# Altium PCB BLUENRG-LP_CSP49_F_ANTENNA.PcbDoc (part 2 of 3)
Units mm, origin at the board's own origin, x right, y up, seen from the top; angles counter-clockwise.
Board outline 90.84 x 54.03 mm, 4 copper layers (Top Layer, G1, G2, Bottom Layer), stack 1.697 mm thick; 159 components, 123 nets, 503 pads, 685 vias.

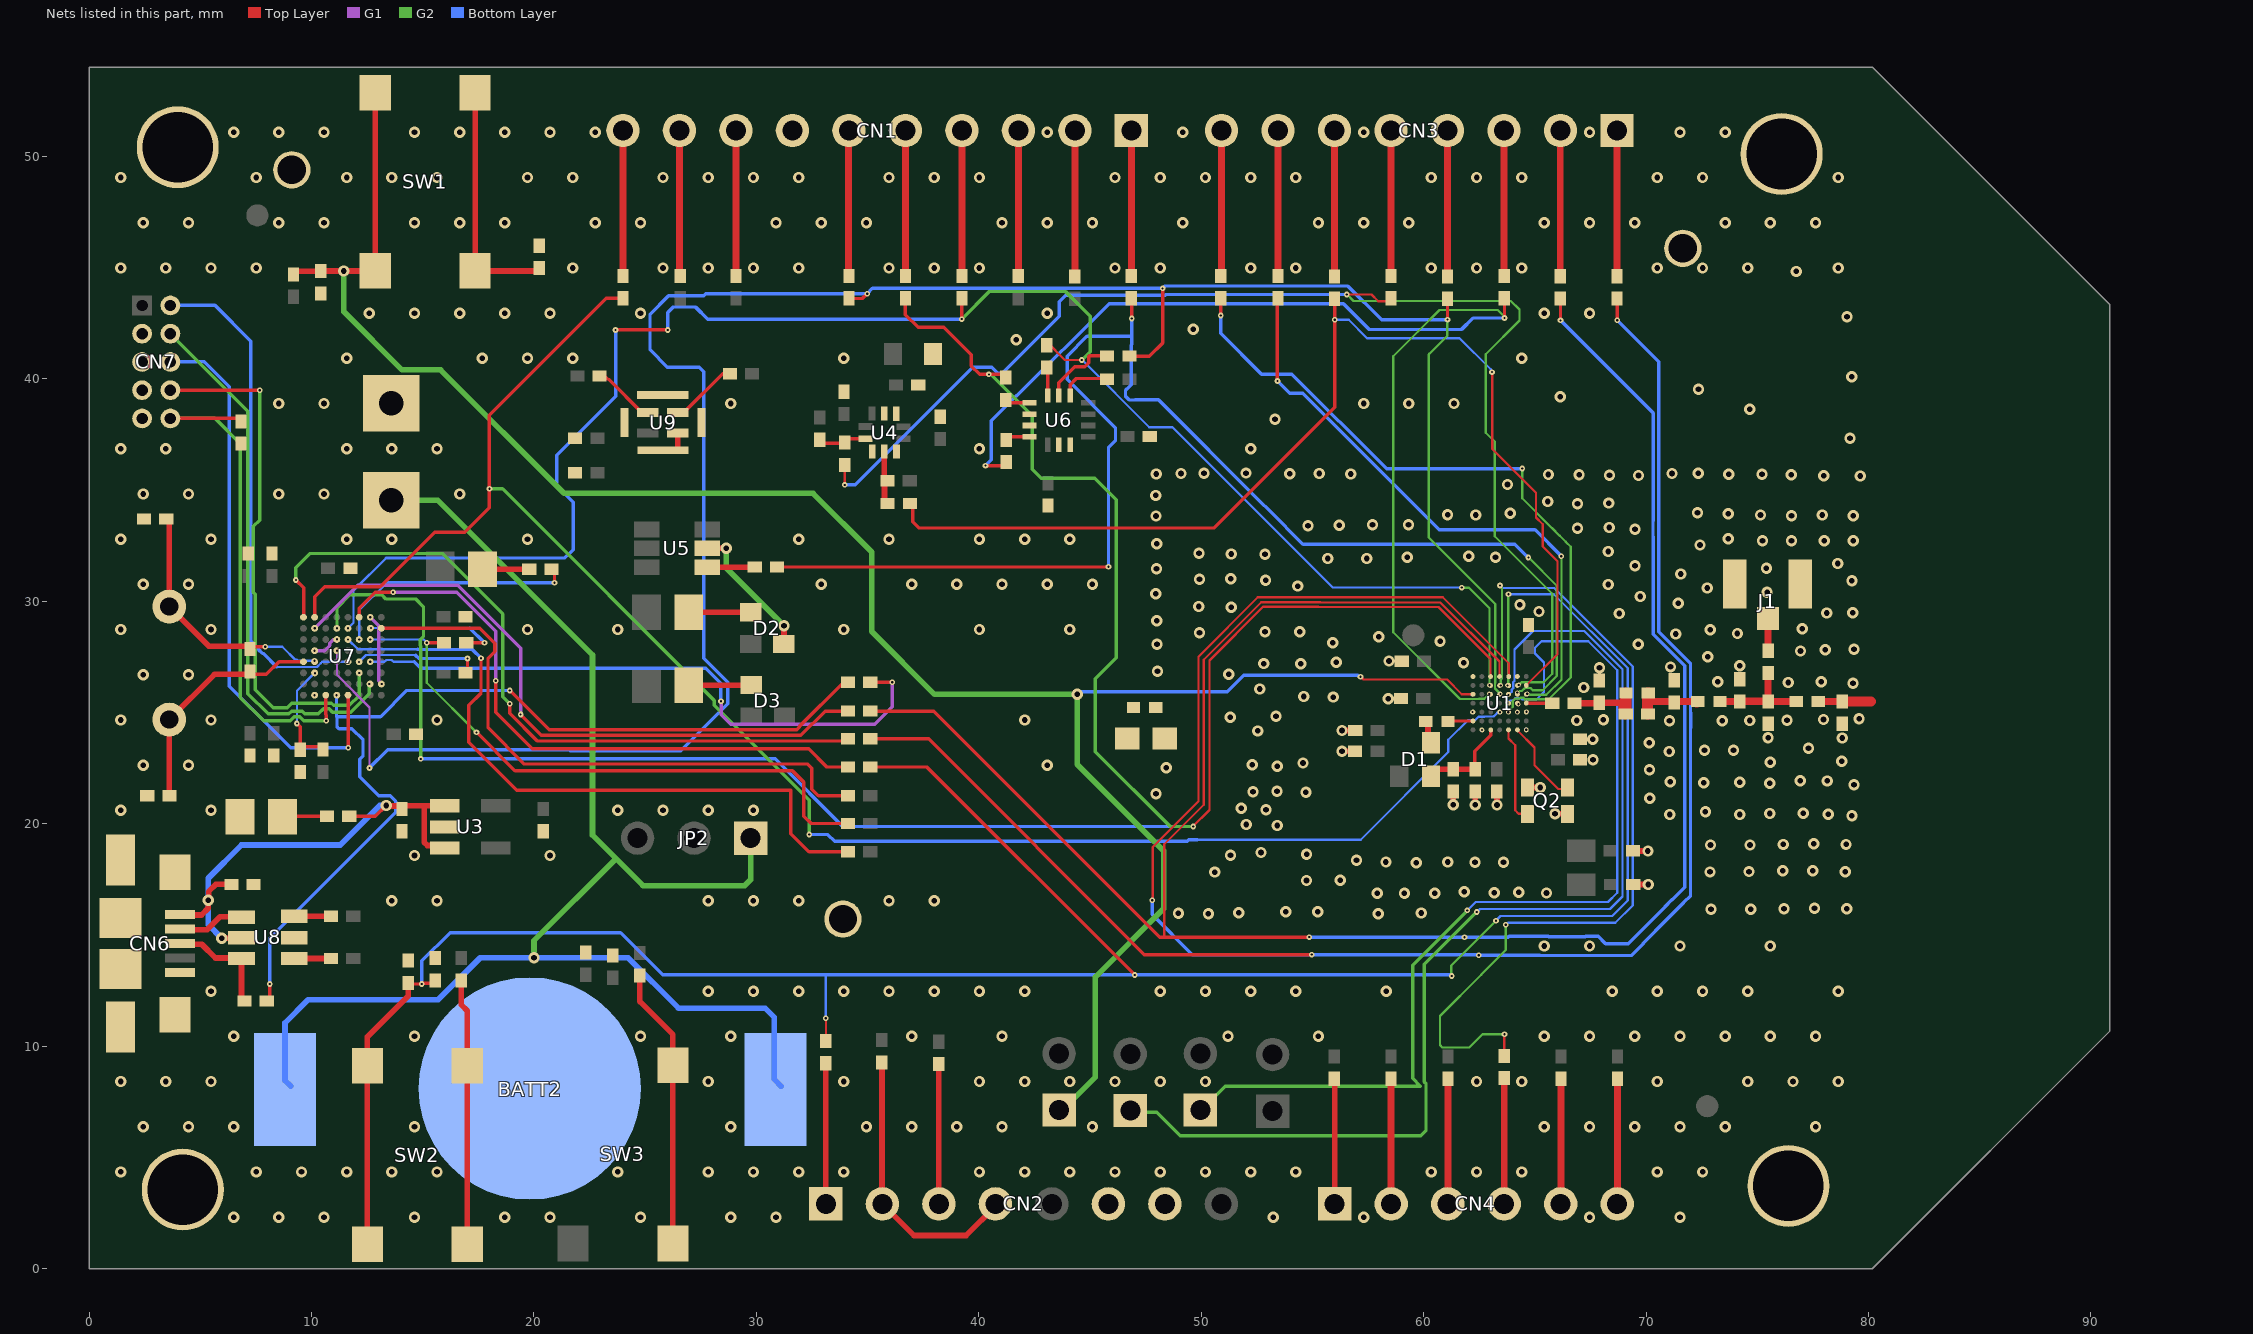
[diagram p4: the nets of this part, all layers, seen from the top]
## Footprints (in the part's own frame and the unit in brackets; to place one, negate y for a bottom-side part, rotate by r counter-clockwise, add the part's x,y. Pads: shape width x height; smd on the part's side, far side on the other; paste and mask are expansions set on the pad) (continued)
PCBCOMPONENT_1 [mil]
  round 12 smd paste+0 mask+0: A1(68.95,-68.95) A2(49.25,-68.95) A3(29.55,-68.95) A4(9.85,-68.95) A5(-9.85,-68.95) A6(-29.55,-68.95) A7(-49.25,-68.95) A8(-68.95,-68.95) B1(68.95,-49.25) B2(49.25,-49.25) B3(29.55,-49.25) B4(9.85,-49.25) B5(-9.85,-49.25) B6(-29.55,-49.25) B7(-49.25,-49.25) B8(-68.95,-49.25) C1(68.95,-29.55) C2(49.25,-29.55) C3(29.55,-29.55) C4(9.85,-29.55) C5(-9.85,-29.55) C6(-29.55,-29.55) C7(-49.25,-29.55) C8(-68.95,-29.55) D1(68.95,-9.85) D2(49.25,-9.85) D3(29.55,-9.85) D4(9.85,-9.85) D5(-9.85,-9.85) D6(-29.55,-9.85) D7(-49.25,-9.85) D8(-68.95,-9.85) E1(68.95,9.85) E2(49.25,9.85) E3(29.55,9.85) E4(9.85,9.85) E5(-9.85,9.85) E6(-29.55,9.85) E7(-49.25,9.85) E8(-68.95,9.85) F1(68.95,29.55) F2(49.25,29.55) F3(29.55,29.55) F4(9.85,29.55) F5(-9.85,29.55) F6(-29.55,29.55) F7(-49.25,29.55) F8(-68.95,29.55) G1(68.95,49.25) G2(49.25,49.25) G3(29.55,49.25) G4(9.85,49.25) G5(-9.85,49.25) G6(-29.55,49.25) G7(-49.25,49.25) G8(-68.95,49.25) H1(68.95,68.95) H2(49.25,68.95) H3(29.55,68.95) H4(9.85,68.95) H5(-9.85,68.95) H6(-29.55,68.95) H7(-49.25,68.95) H8(-68.95,68.95)
  silkscreen extent -98,-97 98,97, body extent -75,-75 75,75, height 20
QUARZO [mil]
  round 60 hole 32: 1(0,0) 2(200,0)
  silkscreen extent -99,-94 299,94, body extent -103,-98 303,98, height 80
"SMD _LED" [mm]
  rect 1.3x1.6 smd: 1(0.948,0.006) 2(-0.952,0.006)
  silkscreen extent -2.13,-1.14 2,1.16, body extent -1.52,-0.64 1.52,0.64, height 1.27
SOT23-6L_S [mil]
  rect 23.6x47.23 smd: 1(-37,-42.12) 2(0,-42.12) 3(37.8,-42.12) 4(36.22,51.18) 5(0,51.17) 6(-37,51.17)
  silkscreen extent -78,-55 55,22, body extent -49,-66 50,75, height 20
stlogo [mm]
  silkscreen extent -44.96,50.81 -33.53,56.9
TESTP [mil]
  round 66 hole 50: 1(-50,100)
UFL_SMT [mm]
  rect 1.05x2.2 smd: 1(0.65,0.4) 3(3.6,0.4)
  rect 1x1.05 smd: 2(2.15,-1.15)
  silkscreen extent 0.1,-1.7 4.15,1.55, body extent 0.12,-1.67 4.13,1.5, height 0.76
WLCSP49_REV1 [mm]
  round 0.22 smd paste+0.03: A1(-1.245,1.3) A2(-0.845,1.3) A3(-0.445,1.3) A4(-0.046,1.3) A5(0.353,1.3) A6(0.753,1.3) A7(1.151,1.299) B1(-1.245,0.9) B2(-0.845,0.9) B3(-0.445,0.9) B4(-0.046,0.9) B5(0.353,0.9) B6(0.753,0.9) B7(1.151,0.899) C1(-1.245,0.501) C2(-0.845,0.501) C3(-0.445,0.501) C4(-0.049,0.504) C5(0.351,0.509) C6(0.751,0.509) C7(1.151,0.509) D1(-1.245,0.102) D2(-0.845,0.102) D3(-0.445,0.102) D4(-0.046,0.102) D5(0.353,0.102) D6(0.753,0.102) D7(1.151,0.104) E1(-1.245,-0.298) E2(-0.845,-0.298) E3(-0.445,-0.298) E4(-0.046,-0.298) E5(0.353,-0.298) E6(0.751,-0.306) E7(1.151,-0.306) F1(-1.245,-0.698) F2(-0.845,-0.698) F3(-0.445,-0.698) F4(-0.046,-0.698) F5(0.353,-0.698) F6(0.753,-0.698) F7(1.156,-0.696) G1(-1.244,-1.096) G2(-0.844,-1.096) G3(-0.444,-1.096) G4(-0.044,-1.096) G5(0.356,-1.096) G6(0.756,-1.096) G7(1.156,-1.096)
  silkscreen extent -1.57,-1.57 1.57,1.57, body extent -1.58,-1.58 1.58,1.58, height 0.51

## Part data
BATT2: library part "Battery holder_0"
C1 C2 C3 C4 C5 C6 C7 C8 C9 C10 C11 C12 C13 C14 C15 C17 C18 C19 C27 C28 C30 C31 C32 C33 C34 C35 C36 C39 C42 C43 C44: library part "MURATA GRM36"
C20 C21 C22 C23 C24 C25 C26 C29 C37 C38 C40 C41: library part C, PSpiceTemplate="C^@REFDES %1 %2 ?TOLERANCE[]C^@REFDES[] @VALUE ?IC/IC{}@IC/ ?TOLERANCE[]\n.model C^@REFDES CAP C{}1 DEV{}@TOLERANCE%[]"
CN6: library part "USB micro B_0"
CN7: library part CON10AP
D1 D2 D3: library part DEV3L_0
DL3 DL4: library part Diodo_led
J1: "50 Ohms, SMA Jack Receptacle, Edge Mount, .25µm Gold (Au) Plating", Manufacturer=Molex
JP1 JP3 JP4 JP5: library part Buzzer
L1 L2 L3 L4 L5 L6: library part IND_short
Q1: library part QUARZO
Q2: library part NX3225SA
R1 R2 R3 R4 R5 R6 R7 R8 R9 R10 R11 R12 R13 R14 R15 R16 R17 R18 R19 R20 R21 R22 R23 R24 R25 R26 R27 R28 R30 R31 R32 R33 R35 R37 R38 R39 R41 R42 R43 R44 R45 R46 R47 R48 R49 R50 R51 R52 R53 R54 R55 R56 R57 R58 R59 R60 R61 R62: library part R_Dup1, PSpiceTemplate="R^@REFDES %1 %2 ?TOLERANCE[]R^@REFDES[] @VALUE  ?TOLERANCE[]\n.model R^@REFDES RES R{}1 DEV{}@TOLERANCE%[]"
R29 R34 R36 R40: library part R
ST1: library part STlogo
SW1 SW2 SW3: library part SWITCH-1
TP1 TP2 TP3 TP4: library part "T POINT R"
U1: library part BlueNRG-LP_CSP49_2
U3: "LDLN025 Series 3.3 V 250 mA Surface Mount Fixed Ultra Low Noise LDO - SOT-23-5L", Package="SOT-23-5 STMicroelectronics"
U4: library part LPS25HB
U7: library part STM32F10XRXY, "No Description Available"
U8: library part USBUFxxW6_0
U9: library part MP34DT05-A_0
X1: library part QUARZO_Dup1

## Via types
v1: diameter 0.508, hole 0.254, Top Layer to Bottom Layer, tented both sides, 522 vias
v2: diameter 0.254, hole 0.102, Top Layer to Bottom Layer, tented both sides, 133 vias
v3: diameter 0.203, hole 0.102, Top Layer to Bottom Layer, tented both sides, 30 vias

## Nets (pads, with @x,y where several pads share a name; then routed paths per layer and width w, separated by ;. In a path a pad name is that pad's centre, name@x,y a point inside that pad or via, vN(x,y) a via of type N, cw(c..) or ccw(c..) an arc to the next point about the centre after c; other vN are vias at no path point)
BLE_RSTN: C20.2 JP5.1 R26.2 SW1.3 SW1.4 U1.A5 | length 96.4
  Top Layer w0.102: R26.2@9.195,44.831 R26.2@9.212,44.848 ; C20.2@10.414,44.848 C20.2@10.422,44.856 ; SW1.4@12.866,44.856 SW1.4@12.867,44.858 ; v2@57.166,26.623 57.301,26.488 61.06,26.488 61.719,25.828 62.201,25.828 U1.A5@62.206,25.823
  Top Layer w0.152: U1.A5@62.206,25.823 U1.A5@62.219,25.823
  Top Layer w0.254: R26.2@9.212,44.848 C20.2@10.414,44.848 ; C20.2@10.422,44.856 v1(11.455,44.856) ; v1@11.459,44.856 SW1.4@12.866,44.856 ; SW1.4@12.867,44.858 SW1.3@12.867,52.868
  G2 w0.254: v1(11.455,44.856) 11.455,43.029 14.073,40.411 15.809,40.411 21.364,34.856 32.555,34.856 35.189,32.222 35.189,28.651 38.019,25.822 v1(44.422,25.822) 44.422,22.68 48.316,18.786 48.316,16.187 45.242,13.114 45.242,8.616 JP5.1@43.675,7.048
  Bottom Layer w0.152: v1(44.422,25.822) 44.539,25.938 51.164,25.938 51.731,26.506 51.735,26.506 51.905,26.675 57.047,26.675 v2@57.092,26.63
  other v2: 57.163,26.615
BLE_SWCLK: JP3.1 U1.E4 | length 44.9
  G2 w0.152: JP3.1@49.949,7.074 51.084,8.209 59.855,8.209 59.507,8.558 59.507,13.636 60.946,15.076 60.946,15.089 61.235,15.378 61.239,15.378 v2@61.964,16.102
  Bottom Layer w0.102: v2(61.958,16.108) v2@61.964,16.104 ; v2@61.961,16.102 v2@61.964,16.104 ; v2@61.97,16.098 v2@61.964,16.104 ; v3@63.791,25.423 63.791,25.44 63.894,25.543 64.015,25.543 64.122,25.65 64.375,25.65 64.425,25.6 65.084,25.6 65.409,25.925 65.409,27.253 65.006,27.656 65.006,27.914 65.3,28.208 67.397,28.208 68.703,26.901 68.703,16.901 68.286,16.483 62.343,16.483 v2@61.964,16.104
  other v3: 63.756,25.437
BLE_SWDIO: JP4.1 U1.E5 | length 49.7
  G2 w0.152: JP4.1@46.838,7.036 48.006,7.036 49.06,5.982 59.873,5.982 60.109,6.218 60.109,8.314 60.03,8.393 60.03,13.689 v2@62.365,16.024
  Bottom Layer w0.102: v2@62.397,16.032 62.539,16.174 68.381,16.174 68.943,16.737 68.943,26.949 67.226,28.666 64.918,28.666 64.085,27.834 64.085,26.423 64.026,26.364 64.026,26.085 64.021,26.09 63.96,26.029 63.96,25.941 v3(63.815,25.797)
  other v2: 62.391,16.036
BOOT0: CN7.10 R58.2 U7.A6 | length 23.8
  Top Layer w0.152: CN7.10@3.658,38.227 R58.2@6.833,38.227 ; U7.A6@10.643,25.786 10.643,24.919 10.668,24.894 v2(10.668,24.638)
  G2 w0.152: CN7.10@3.658,38.227 5.664,38.227 6.807,37.084 6.807,25.679 7.849,24.638 9.043,24.638 9.221,24.816 9.473,24.816 9.651,24.638 v2(10.668,24.638)
DM: CN6.2 U8.4 | length 2.9
  Top Layer w0.254: CN6.2@4.293,15.24 5.309,15.24 5.893,15.824 6.706,15.824 U8.4@6.853,15.677
DP: CN6.3 R43.2 U8.6 | length 4.7
  Top Layer w0.254: CN6.3@4.293,14.59 5.069,14.59 5.69,13.97 6.701,13.97 6.858,13.813 R43.2@6.858,12.04
DP-CON: R43.1 R59.2 U7.A5 | length 42.9
  Top Layer w0.152: v2@8.125,12.802 v2(8.128,12.799) R43.1@8.128,12.04 ; v2(18.92,25.997) 20.686,24.232 31.823,24.232 31.933,24.341 31.933,24.376 33.922,26.365 R59.2@33.985,26.365
  Bottom Layer w0.152: v2(8.128,12.799) 8.128,14.859 13.792,20.523 13.792,21.007 13.539,21.26 13.03,21.26 12.167,22.123 12.167,22.911 12.319,23.063 12.319,23.774 11.811,24.282 11.237,24.282 11.148,24.372 11.148,24.816 ; v2(11.125,25.781) 11.125,24.839 11.148,24.816 ; v2(18.92,25.997) 14.288,25.997 13.107,24.816 11.148,24.816
GND: BATT1.2 BATT2.3 C17.1 C19.1 C20.1 C21.1 C22.1 C23.1 C24.1 C25.1 C26.1 C27.2 C28.2 C29.2 C31.1 C32.1 C33.1 C34.1 C35.1 C36.1 C37.1 C38.1 C39.1 C40.1 C41.1 CN1.7 CN2.6 CN2.7 CN6.5 CN6.6 CN6.7 CN6.8 CN6.9 CN6.10 CN6.11 CN7.3 CN7.5 CN7.7 CN7.9 DL1.2 L2.1 L6.1 R28.2 R31.2 R32.2 R52.1 R58.1 TP1.1 TP2.1 TP3.1 U3.2 U4.3 U4.5 U4.8 U4.9 U6.2 U6.3 U6.6 U6.7 U7.A7 U7.B1 U7.E7 U7.F5 U7.H2 U8.2 U9.2 U9.5 U9.6 U9.7 U9.8 V1.1 V2.1 V3.1 V4.1 | length 5.9
  Top Layer w0.102: U9.7@25.806,36.792 U9.7@26.467,36.792
  Top Layer w0.254: U9.7@26.467,36.792 U9.2@26.467,37.579
  G1 w0.152: v2(10.135,27.788) 10.592,27.788 10.82,28.016 10.82,28.118 10.979,28.276 11.131,28.276 v2(11.151,28.296) ; v2(12.649,29.286) 13.03,28.905 13.03,26.429 13.157,26.302 v2(13.157,26.289)
  other v1: 6.502,2.32 8.534,2.32 10.566,2.32 14.63,2.32 18.694,2.32 20.726,2.32 24.79,2.32 28.854,2.32 30.886,2.32 53.238,2.32 57.302,2.32 67.462,2.32 71.526,2.32 1.422,4.352 7.518,4.352 9.55,4.352 11.582,4.352 13.614,4.352 15.646,4.352 23.774,4.352 27.838,4.352 29.87,4.352 31.902,4.352 33.934,4.352 40.03,4.352 42.062,4.352 44.094,4.352 46.126,4.352 48.158,4.352 50.19,4.352 52.222,4.352 54.254,4.352 60.35,4.352 62.382,4.352 64.414,4.352 70.51,4.352 72.542,4.352 2.438,6.384 4.47,6.384 6.502,6.384 14.63,6.384 28.854,6.384 34.95,6.384 36.982,6.384 39.014,6.384 41.046,6.384 45.11,6.384 65.43,6.384 67.462,6.384 69.494,6.384 71.526,6.384 73.558,6.384 77.622,6.384 1.422,8.416 3.454,8.416 5.486,8.416 27.838,8.416 33.934,8.416 40.03,8.416 42.062,8.416 44.094,8.416 46.126,8.416 48.158,8.416 50.19,8.416 62.382,8.416 64.414,8.416 70.51,8.416 74.574,8.416 76.606,8.416 78.638,8.416 6.502,10.448 14.63,10.448 24.79,10.448 28.854,10.448 36.982,10.448 41.046,10.448 51.206,10.448 55.27,10.448 65.43,10.448 67.462,10.448 69.494,10.448 71.526,10.448 73.558,10.448 75.59,10.448 77.622,10.448 5.486,12.48 27.838,12.48 29.87,12.48 31.902,12.48 33.934,12.48 35.966,12.48 37.998,12.48 40.03,12.48 42.062,12.48 48.158,12.48 50.19,12.48 52.222,12.48 54.254,12.48 58.318,12.48 68.478,12.48 70.51,12.48 72.542,12.48 74.574,12.48 78.638,12.48 65.43,14.512 67.462,14.512 71.526,14.512 75.59,14.512 13.614,16.544 15.646,16.544 27.838,16.544 29.87,16.544 31.902,16.544 35.966,16.544 37.998,16.544 14.63,18.576 20.726,18.576 1.422,20.608 5.486,20.608 23.774,20.608 25.806,20.608 27.838,20.608 29.87,20.608 2.438,22.64 4.47,22.64 43.078,22.64 1.422,24.672 5.486,24.672 15.646,24.672 42.062,24.672 2.438,26.704 4.47,26.704 1.422,28.736 5.486,28.736 19.71,28.736 23.774,28.736 33.934,28.736 40.03,28.736 44.094,28.736 2.438,30.768 4.47,30.768 32.918,30.768 36.982,30.768 39.014,30.768 41.046,30.768 43.078,30.768 45.11,30.768 1.422,32.8 5.486,32.8 11.582,32.8 13.614,32.8 19.71,32.8 31.902,32.8 35.966,32.8 40.03,32.8 42.062,32.8 44.094,32.8 2.438,34.832 4.47,34.832 8.534,34.832 10.566,34.832 16.662,34.832 1.422,36.864 3.454,36.864 11.582,36.864 13.614,36.864 15.646,36.864 40.03,36.864 52.222,36.864 79.167,37.341 53.319,38.189 74.665,38.639 8.534,38.896 10.566,38.896 28.854,38.896 57.302,38.896 59.334,38.896 61.366,38.896 66.137,39.195 72.361,39.539 79.246,40.095 11.582,40.928 17.678,40.928 19.71,40.928 21.742,40.928 33.934,40.928 64.414,40.928 41.692,41.764 49.637,42.241 79.035,42.797 12.598,42.96 14.63,42.96 16.662,42.96 18.694,42.96 20.726,42.96 24.79,42.96 43.078,42.96 65.43,42.96 67.462,42.96 76.757,44.836 1.422,44.992 3.454,44.992 5.486,44.992 7.518,44.992 21.742,44.992 25.806,44.992 27.838,44.992 29.87,44.992 31.902,44.992 35.966,44.992 37.998,44.992 40.03,44.992 46.126,44.992 48.158,44.992 52.222,44.992 54.254,44.992 60.35,44.992 62.382,44.992 64.414,44.992 70.51,44.992 72.542,44.992 74.574,44.992 78.638,44.992 2.438,47.024 4.47,47.024 8.534,47.024 10.566,47.024 14.63,47.024 16.662,47.024 18.694,47.024 22.758,47.024 24.79,47.024 30.886,47.024 32.918,47.024 34.95,47.024 41.046,47.024 43.078,47.024 45.11,47.024 49.174,47.024 55.27,47.024 57.302,47.024 59.334,47.024 65.43,47.024 67.462,47.024 69.494,47.024 73.558,47.024 75.59,47.024 77.622,47.024 1.422,49.056 7.518,49.056 11.582,49.056 13.614,49.056 15.646,49.056 19.71,49.056 21.742,49.056 25.806,49.056 27.838,49.056 29.87,49.056 31.902,49.056 35.966,49.056 37.998,49.056 40.03,49.056 46.126,49.056 48.158,49.056 50.19,49.056 52.222,49.056 54.254,49.056 60.35,49.056 62.382,49.056 64.414,49.056 70.51,49.056 72.542,49.056 78.638,49.056 6.502,51.088 8.534,51.088 10.566,51.088 14.63,51.088 16.662,51.088 18.694,51.088 20.726,51.088 22.758,51.088 43.078,51.088 49.174,51.088 57.302,51.088 67.462,51.088 71.526,51.088 73.558,51.088
  other v2: 10.135,25.781
GND_RF: C1.1 C2.1 C3.1 C4.1 C5.1 C6.1 C7.1 C8.1 C9.1 C10.1 C11.1 C12.1 C14.1 C15.1 C18.1 C42.1 C43.1 J1.1 J1.3 L2.2 L6.2 Q2.2 Q2.4 U1.A3 U1.A7 U1.B1 U1.F3 U1.F4 U1.F7 U1.G1 U1.G3 | length 5.7
  Top Layer w0.152: v1@56.322,24.211 v1@56.334,24.199 ; C9.1@56.926,23.268 C9.1@56.93,23.271 ; v1(58.413,25.626) v1@58.428,25.611 ; C12.1@59.01,27.306 C12.1@59.024,27.32 ; v1(61.333,20.861) v1@61.336,20.865 ; C3.1@62.317,21.424 C3.1@62.34,21.447 ; C7.1@63.291,21.424 C7.1@63.301,21.414 ; Q2.2@64.724,21.603 Q2.2@64.757,21.636 ; Q2.4@66.498,20.456 Q2.4@66.505,20.462 ; C11.1@67.036,23.806 C11.1@67.041,23.801 ; C10.1@67.051,22.876 C10.1@67.052,22.878 ; C1.1@69.41,18.787 C1.1@69.415,18.782 ; v1@70.077,18.782 v1@70.096,18.764 ; v1@70.085,17.274 v1@70.09,17.269
  Top Layer w0.254: v1(56.33,23.268) C9.1@56.926,23.268 ; v1@56.334,24.199 C8.1@56.924,24.199 ; v1@58.433,27.306 58.441,27.314 v1(58.441,27.32) ; C15.1@58.932,25.611 C15.1@58.968,25.647 ; v1@61.336,20.865 C4.1@61.336,21.454 ; v1(62.317,20.851) C3.1@62.317,21.424 ; v1(63.301,20.845) C7.1@63.301,21.414 ; Q2.2@64.757,21.636 v1(65.245,21.636) ; v1(65.906,20.456) Q2.4@66.498,20.456 ; C1.1@69.415,18.782 v1@70.077,18.782 ; C2.1@69.424,17.274 v1@70.085,17.274
  G1 w0.102: v3(64.628,25.035) v3@64.63,25.033
  G1 w0.152: v3@62.615,24.216 v3(62.628,24.216) ; v3(64.617,24.227) v3@64.628,24.215 ; v3@64.621,24.244 v3@64.621,24.251
  Bottom Layer w0.152: v3@64.605,25.025 64.631,25.025 v3@64.634,25.022
  other v1: 50.325,15.957 57.963,15.953 48.976,15.987 59.899,15.995 51.689,16.002 53.797,16.053 55.245,16.053 72.923,16.154 74.701,16.154 76.2,16.18 79.019,16.18 77.572,16.205 57.92,16.883 59.137,16.875 60.505,16.875 63.173,16.9 65.523,16.894 64.281,16.925 61.831,16.942 70.094,17.274 54.733,17.453 56.254,17.468 50.607,17.831 72.878,17.84 78.95,17.84 74.627,17.854 76.141,17.895 77.491,17.895 59.674,18.252 62.309,18.277 63.593,18.268 58.306,18.285 61.092,18.285 56.981,18.365 51.316,18.588 54.74,18.638 52.687,18.715 70.085,18.782 72.898,19.05 74.676,19.05 76.175,19.075 78.994,19.075 77.546,19.101 53.424,19.927 52.032,19.968 79.256,20.363 71.069,20.422 74.219,20.422 78.193,20.425 75.561,20.465 77.067,20.475 72.669,20.549 52.917,20.64 51.799,20.701 70.161,21.144 47.967,21.356 54.709,21.425 52.327,21.448 53.41,21.469 79.353,21.752 75.561,21.831 72.593,21.844 74.219,21.869 71.095,21.895 76.937,21.94 78.153,21.93 70.156,22.435 48.43,22.523 53.424,22.593 52.299,22.657 54.575,22.737 75.58,22.773 78.801,22.811 67.617,22.878 71.047,23.255 72.629,23.313 73.932,23.314 77.303,23.399 70.151,23.645 67.605,23.801 78.815,23.86 75.487,23.872 52.542,24.178 56.33,24.199 66.888,24.646 71.058,24.641 73.427,24.641 74.661,24.645 76.34,24.659 68.084,24.68 77.975,24.689 79.578,24.72 51.313,24.792 53.362,24.834 55.935,25.699 54.615,25.727 52.629,26.06 67.206,26.133 79.306,26.323 76.389,26.353 73.23,26.389 77.878,26.389 51.243,26.725 48.035,26.867 67.906,27.013 71.103,27.055 74.216,27.11 54.478,27.198 52.819,27.205 61.797,27.248 56.068,27.26 72.768,27.507 76.941,27.771 78.06,27.828 79.353,27.848 48.013,28.068 69.651,28.079 55.917,28.144 60.741,28.205 57.985,28.411 71.337,28.533 74.108,28.557 49.926,28.585 52.871,28.633 54.436,28.633 72.886,28.732 77.029,28.771 47.998,29.134 68.791,29.456 78.123,29.476 79.295,29.487 65.185,29.55 51.359,29.743 49.886,29.769 64.33,29.844 71.453,29.919 69.746,30.222 47.963,30.342 75.442,30.413 72.748,30.603 54.345,30.69 68.301,30.759 52.896,30.948 79.256,30.934 49.926,30.998 51.333,31.013 71.561,31.232 47.991,31.465 75.412,31.49 69.504,31.604 78.62,31.706 55.688,31.928 57.443,31.928 59.269,31.987 63.232,31.985 62.031,32.032 52.871,32.117 51.359,32.131 49.901,32.167 68.308,32.241 72.423,32.535 48.005,32.595 75.233,32.726 76.536,32.728 78.01,32.726 79.314,32.728 73.701,32.824 69.504,33.24 66.919,33.283 68.346,33.322 54.804,33.402 56.212,33.426 57.705,33.443 59.321,33.441 47.97,33.838 76.536,33.847 79.314,33.847 61.079,33.892 62.349,33.884 75.147,33.885 77.925,33.885 73.701,33.943 63.889,33.969 72.312,33.982 66.919,34.392 68.327,34.421 65.583,34.493 47.964,34.765 63.773,35.254 77.991,35.654 79.63,35.64 68.357,35.668 69.663,35.663 65.61,35.705 66.99,35.691 76.522,35.697 47.976,35.728 56.72,35.728 73.722,35.72 75.215,35.712 49.094,35.749 53.977,35.736 55.312,35.752 71.167,35.752 72.342,35.757 50.125,35.762 52.018,35.77
  other v3: 62.196,25.026 64.216,25.02 64.264,25.38
GREEN: D2.3 U5.5 | length 6.2
  Top Layer w0.254: U5.5@27.79,32.385 v1(28.651,32.385) ; D2.3@31.242,28.092 v1(31.242,28.905)
  G2 w0.254: v1(28.651,32.385) 28.651,31.496 v1(31.242,28.905)
JTCK: CN7.4 U7.B2 | length 24.5
  G2 w0.152: CN7.4@3.658,42.037 7.137,38.557 7.137,25.857 8.052,24.943 8.989,24.943 9.116,25.07 9.579,25.07 9.706,24.943 10.313,24.943 10.542,25.171 10.794,25.171 10.947,25.019 11.76,25.019 12.598,25.857 v2(12.598,26.289)
JTDI: CN7.8 U7.C3 | length 24
  Top Layer w0.152: CN7.8@3.658,39.497 v2(7.671,39.497)
  G2 w0.152: v2(7.671,39.497) 7.671,33.655 7.391,33.376 7.391,30.4 7.468,30.324 7.468,26.035 8.28,25.222 8.909,25.222 9.112,25.425 10.899,25.425 10.999,25.326 11.708,25.326 12.149,25.767 v2(12.149,26.787)
JTDO: CN7.6 U7.A4 | length 25.4
  Top Layer w0.102: v2@11.648,23.429 v2(11.659,23.419)
  Top Layer w0.152: v2@11.648,23.429 U7.A4@11.648,25.786
  Bottom Layer w0.152: CN7.6@3.658,40.767 5.182,40.767 6.299,39.649 6.299,26.187 9.068,23.419 v2(11.659,23.419)
JTMS: CN7.2 U7.D4 | length 22.7
  Bottom Layer w0.102: 8.444,27.051 10.25,27.051 10.414,27.215 10.414,27.217 10.484,27.287 v2(11.648,27.287)
  Bottom Layer w0.152: CN7.2@3.658,43.307 5.664,43.307 7.264,41.707 7.264,28.231 7.62,27.875 7.62,27.839 7.799,27.661 7.834,27.661 8.444,27.051
NetBATT1_1: BATT1.1 BATT2.1 BATT2.2 JP2.1 | length 66.7
  G2 w0.152: BATT1.1@13.589,34.544 BATT1.1@13.846,34.287
  G2 w0.254: BATT1.1@13.846,34.287 14.369,34.287 14.625,34.544 15.682,34.544 22.635,27.591 22.635,19.494 24.908,17.221 29.477,17.221 29.743,17.487 JP2.1@29.743,19.355 JP2.1@29.743,19.406 ; v1(20.008,13.98) 20.008,14.75 23.658,18.4
  Bottom Layer w0.254: BATT2.2@9.075,8.204 8.814,8.465 8.814,11.054 9.85,12.09 15.697,12.09 17.587,13.98 v1(20.008,13.98) 24.237,13.98 26.502,11.714 30.396,11.714 30.81,11.3 30.81,8.511 BATT2.1@31.117,8.204
NetC3_2: C3.2 C4.2 D1.1 U1.C1 | length 4
  Top Layer w0.152: D1.1@60.447,22.345 D1.1@60.556,22.455 ; C3.2@62.272,22.455 C3.2@62.3,22.483 ; C3.2@62.3,22.429 C3.2@62.3,22.483 ; C3.2@62.312,22.495 C3.2@62.3,22.483 ; U1.C1@63.019,24.225 63.019,23.977 62.3,23.259 C3.2@62.3,22.483
  Top Layer w0.254: D1.1@60.556,22.455 C4.2@61.339,22.455 C3.2@62.272,22.455
NetC5_2: C5.2 C13.2 C30.1 L1.1 | length 3.7
  Top Layer w0.305: C30.1@66.784,25.425 C5.2@67.913,25.425 ; C5.2@67.929,25.44 69.019,25.44
  Top Layer w0.508: C5.2@67.913,25.425 67.929,25.44 C5.2@67.936,25.447 ; 69.019,25.44 69.019,25.366 69.019,25.217 69.094,25.143 C13.2@69.094,24.995 ; C13.2@69.077,24.953 69.097,24.973 L1.1@69.097,25.885
NetC6_2: C6.2 C13.1 L1.2 L5.1 | length 3.1
  Top Layer w0.305: 70.072,25.496 71.132,25.496 L5.1@72.274,25.496
  Top Layer w0.508: C13.1@70.068,25.006 70.068,25.881 70.072,25.885 L1.2@70.097,25.885 ; C13.1@70.072,24.953 C13.1@70.086,24.939 ; L5.1@72.274,25.496 L5.1@72.278,25.5
NetC17_2: C17.2 C29.1 CN6.1 R29.2 U3.1 U3.3 U8.5 | length 23.8
  Top Layer w0.102: CN6.1@4.089,15.92 4.218,16.049 4.376,16.049 CN6.1@4.524,15.9 ; v1(5.359,16.561) v1@5.376,16.577 ; v1@13.335,20.803 v1(13.36,20.828)
  Top Layer w0.152: R29.2@11.836,20.345 12.878,20.345 v1@13.335,20.803
  Top Layer w0.254: CN6.1@4.524,15.9 5.055,15.9 5.359,16.205 v1(5.359,16.561) ; v1@5.376,16.577 5.376,16.958 5.698,17.281 6.392,17.281 C29.1@6.401,17.272 ; v1(5.969,14.859) 6.778,14.859 U8.5@6.828,14.91 ; v1@13.335,20.803 14.072,20.803 14.077,20.808 15.075,20.808 ; U3.3@16.078,18.913 15.966,19.025 15.211,19.025 15.075,19.161 15.075,20.808 ; U3.1@16.078,20.813 16.073,20.808 15.075,20.808
  Bottom Layer w0.254: v1(5.969,14.859) 5.359,15.469 v1(5.359,16.561) 5.359,17.556 6.85,19.047 11.293,19.047 13.073,20.828 v1(13.36,20.828)
NetC18_2: C18.2 C42.2 C44.1 L3.1 L5.2 | length 4.7
  Top Layer w0.152: C42.2@75.463,25.476 C42.2@75.489,25.502
  Top Layer w0.305: L5.2@73.324,25.504 C18.2@74.157,25.504 ; C44.1@75.489,26.78 C42.2@75.489,25.502 L3.1@76.749,25.502
  Top Layer w0.33: C18.2@74.213,25.512 C42.2@75.473,25.512
  Top Layer w0.508: C18.2@74.157,25.504 C18.2@74.183,25.529 ; C18.2@74.213,25.499 C18.2@74.213,25.512 ; C42.2@75.461,25.493 C42.2@75.472,25.503
NetC30_2: C30.2 U1.G4 | length 1.2
  Top Layer w0.152: U1.G4@64.615,25.427 65.777,25.426 C30.2@65.781,25.422
  Top Layer w0.254: C30.2@65.645,25.421 C30.2@65.646,25.422
NetC43_2: C43.2 L3.2 | length 2.4
  Top Layer w0.305: L3.2@77.749,25.502 C43.2@78.816,25.502
  Top Layer w0.457: C43.2@78.816,25.502 80.119,25.502
NetC44_2: C44.2 J1.2 | length 1.5
  Top Layer w0.305: C44.2@75.489,27.78 J1.2@75.489,29.235
NetCN1_1: CN1.1 R11.2 | length 6.5
  Top Layer w0.305: R11.2@46.863,44.624 R11.2@46.863,44.632 CN1.1@46.863,51.171
NetCN1_2: CN1.2 R10.2 | length 6.6
  Top Layer w0.305: R10.2@44.323,44.61 CN1.2@44.323,51.171
NetCN1_3: CN1.3 R8.2 | length 6.5
  Top Layer w0.305: R8.2@41.783,44.628 R8.2@41.783,44.632 CN1.3@41.783,51.171
NetCN1_4: CN1.4 R7.2 | length 6.5
  Top Layer w0.305: R7.2@39.243,44.67 CN1.4@39.243,51.171
NetCN1_5: CN1.5 R6.2 | length 6.5
  Top Layer w0.305: R6.2@36.703,44.632 CN1.5@36.703,51.171
NetCN1_6: CN1.6 R4.2 | length 6.6
  Top Layer w0.305: R4.2@34.15,44.624 34.15,51.158 CN1.6@34.163,51.171
NetCN1_8: CN1.8 R3.2 | length 6.5
  Top Layer w0.305: R3.2@29.083,44.632 CN1.8@29.083,51.171
NetCN1_9: CN1.9 R2.2 | length 6.6
  Top Layer w0.305: R2.2@26.543,44.61 CN1.9@26.543,51.171
NetCN1_10: CN1.10 R1.2 | length 6.6
  Top Layer w0.305: R1.2@24.003,44.614 R1.2@24.003,44.632 CN1.10@24.003,51.171
NetCN2_1: CN2.1 R62.1 | length 6.1
  Top Layer w0.102: R62.1@33.126,9.026 R62.1@33.131,9.031
  Top Layer w0.254: CN2.1@33.126,2.916 33.126,6.017 ; 33.126,6.751 R62.1@33.126,9.026 ; 33.126,6.017 33.126,6.751
NetCN2_2: CN2.2 CN2.4 R5.1 | length 12.6
  Top Layer w0.254: R5.1@35.636,9.144 35.651,9.129 35.651,2.931 CN2.2@35.666,2.916 37.091,1.491 39.431,1.491 40.746,2.806 CN2.4@40.746,2.916
NetCN2_3: CN2.3 R9.1 | length 6.7
  Top Layer w0.254: CN2.3@37.8,2.916 CN2.3@38.206,2.916 R9.1@38.206,9.013 ; R9.1@38.1,9.042 R9.1@38.206,8.937
NetCN3_1: CN3.1 R24.2 | length 6.4
  Top Layer w0.305: CN3.1@68.693,51.171 68.694,51.169 68.694,44.755 R24.2@68.694,44.752
NetCN3_2: CN3.2 R22.2 | length 6.4
  Top Layer w0.305: R22.2@66.142,44.755 66.142,51.16 CN3.2@66.153,51.171
NetCN3_3: CN3.3 R20.2 | length 6.4
  Top Layer w0.152: R20.2@63.613,44.782 R20.2@63.627,44.767
  Top Layer w0.305: R20.2@63.613,44.782 CN3.3@63.613,51.171
NetCN3_4: CN3.4 R18.2 | length 6.4
  Top Layer w0.305: CN3.4@61.073,51.171 61.074,51.169 R18.2@61.074,44.742
NetCN3_5: CN3.5 R16.2 | length 6.4
  Top Layer w0.305: CN3.5@58.533,51.171 58.534,51.169 R16.2@58.534,44.767
NetCN3_6: CN3.6 R13.2 | length 6.4
  Top Layer w0.305: CN3.6@55.993,51.171 55.994,51.169 R13.2@55.994,44.742
NetCN3_7: CN3.7 R14.2 | length 6.4
  Top Layer w0.305: CN3.7@53.453,51.171 53.454,51.169 R14.2@53.454,44.767
NetCN3_8: CN3.8 R12.2 | length 6.5
  Top Layer w0.305: R12.2@50.913,44.624 CN3.8@50.913,51.171
NetCN4_1: CN4.1 R15.1 | length 5.5
  Top Layer w0.152: R15.1@55.982,8.407 R15.1@56.004,8.385
  Top Layer w0.254: CN4.1@56.004,2.916 R15.1@56.004,8.385
NetCN4_2: CN4.2 R17.1 | length 5.5
  Top Layer w0.305: R17.1@58.534,8.407 58.534,2.926 CN4.2@58.544,2.916
NetCN4_3: CN4.3 R19.1 | length 5.5
  Top Layer w0.305: CN4.3@61.084,2.916 61.092,2.924 61.092,8.4 R19.1@61.1,8.407
NetCN4_4: CN4.4 R21.1 | length 5.5
  Top Layer w0.305: CN4.4@63.624,2.916 63.626,2.917 63.626,8.432 R21.1@63.627,8.433
NetCN4_5: CN4.5 R23.1 | length 5.5
  Top Layer w0.305: CN4.5@66.164,2.916 66.172,2.924 66.172,8.4 R23.1@66.18,8.407
NetCN4_6: CN4.6 R25.1 | length 5.5
  Top Layer w0.305: CN4.6@68.704,2.916 68.712,2.924 68.712,8.4 R25.1@68.72,8.407
NetD1_2: D1.2 L4.2 | length 1.1
  Top Layer w0.203: L4.2@60.097,24.602 60.134,24.602 L4.2@60.199,24.536
  Top Layer w0.254: L4.2@60.199,24.536 60.199,23.718 D1.2@60.282,23.634
NetD2_2: D2.2 DL2.2 | length 2.8
  Top Layer w0.254: DL2.2@26.95,29.515 D2.2@29.743,29.515
NetD3_2: D3.2 DL3.2 | length 2.8
  Top Layer w0.254: DL3.2@26.949,26.238 D3.2@29.769,26.238
NetDL1_1: DL1.1 R29.1 | length 1.9
  Top Layer w0.102: DL1.1@8.695,20.326 DL1.1@8.714,20.345
  Top Layer w0.152: DL1.1@8.714,20.345 R29.1@10.566,20.345
NetDL4_2: DL4.2 R61.1 | length 1.8
  Top Layer w0.254: DL4.2@17.679,31.445 19.456,31.445
NetL4_1: L4.1 U1.A2 | length 1.1
  Top Layer w0.152: L4.1@61.107,24.61 61.122,24.625 U1.A2@62.219,24.625
NetQ2_1: Q2.1 U1.F1 | length 3.8
  Top Layer w0.102: U1.F1@64.205,24.217 64.205,24.211 64.986,23.43 64.986,22.634 65.376,22.245 ; 65.376,22.244 66.049,21.57 66.351,21.57 Q2.1@66.429,21.649
  Top Layer w0.152: U1.F1@64.217,24.212 U1.F1@64.218,24.226
NetQ2_3: Q2.3 U1.E1 | length 4.4
  Top Layer w0.102: U1.E1@63.818,24.226 63.818,23.835 64.121,23.532 64.121,20.607 64.27,20.458 64.649,20.458 Q2.3@64.69,20.5
NetR27_2: R27.2 SW2.3 SW2.4 | length 11.8
  Top Layer w0.254: R27.2@16.739,12.827 16.739,11.862 17.003,11.597 SW2.4@17.003,9.117 SW2.3@17.003,1.107
NetR28_1: R28.1 SW1.1 SW1.2 | length 10.9
  Top Layer w0.102: R28.1@20.242,44.858 R28.1@20.244,44.856
  Top Layer w0.254: SW1.1@17.357,52.868 SW1.2@17.357,44.858 R28.1@20.242,44.858
NetR30_2: R30.2 SW3.3 SW3.4 | length 12.5
  Top Layer w0.254: R30.2@24.765,13.056 24.765,12.014 26.249,10.53 SW3.4@26.249,9.142 SW3.3@26.249,1.132
NetR33_2: R33.2 R34.2 U4.2 | length 2.1
  Top Layer w0.152: R34.2@32.857,37.119 33.824,37.119 R33.2@33.978,37.273 ; R33.2@34.026,37.306 R33.2@34.055,37.278 ; R33.2@34.034,37.311 34.039,37.307 U4.2@34.907,37.307
NetR35_2: R35.2 R36.2 U4.4 | length 2.3
  Top Layer w0.254: R35.2@35.75,34.365 35.764,34.378 R36.2@35.764,35.429 ; U4.4@35.758,36.735 35.758,35.53 R36.2@35.794,35.494
NetR37_1: R37.1 U6.14 | length 1.1
  Top Layer w0.152: U6.14@43.094,39.255 R37.1@43.094,40.402
  Top Layer w0.254: R37.1@43.094,40.402 R37.1@43.096,40.404
NetR38_1: R38.1 U6.13 | length 3.3
  Top Layer w0.152: U6.13@43.602,39.255 43.602,39.839 44.312,40.549 44.763,40.549 44.941,40.727 44.941,41.018 44.969,41.046 R38.1@45.673,41.046
NetR39_1: R39.1 U6.12 | length 2.1
  Top Layer w0.152: U6.12@44.11,39.255 44.11,39.747 44.385,40.022 R39.1@45.625,40.022
NetR40_1: R40.1 U5.4 | length 2
  Top Layer w0.254: U5.4@27.79,31.535 27.796,31.541 29.788,31.541 R40.1@29.794,31.547
NetR41_2: R41.2 U6.1 | length 1
  Top Layer w0.152: R41.2@41.25,38.917 41.259,38.925 U6.1@42.281,38.925
NetR42_2: R42.2 U6.4 | length 1
  Top Layer w0.152: R42.2@41.257,37.408 42.274,37.408 U6.4@42.281,37.401
NetR45_2: R45.2 U8.1 | length 1.5
  Top Layer w0.254: U8.1@9.223,13.945 R45.2@10.744,13.945
NetR46_2: R46.2 U8.3 | length 1.5
  Top Layer w0.254: U8.3@9.223,15.845 9.226,15.847 10.742,15.847 R46.2@10.744,15.85
NetR47_2: R47.2 U7.H3 | length 27.9
  Top Layer w0.152: U7.H3@12.149,29.289 12.149,29.688 12.875,30.414 v2(13.67,30.414) ; v2(18.288,26.429) 18.288,25.016 19.929,23.376 32.355,23.376 33.175,22.555 R47.2@33.985,22.555
  G1 w0.152: v2(13.67,30.414) 16.525,30.414 18.288,28.651 v2(18.288,26.429)
NetR48_2: R48.2 U7.H8 | length 33.3
  Top Layer w0.152: v2(9.301,30.963) 9.652,30.612 9.652,29.299 U7.H8@9.642,29.289 ; v2(18.913,25.397) 18.913,24.974 20.163,23.724 33.884,23.724 R48.2@33.985,23.825
  G2 w0.152: v2(9.301,30.963) 9.301,31.521 9.936,32.156 15.872,32.156 18.593,29.436 18.593,25.717 v2(18.913,25.397)
NetR49_1: R49.1 U7.G7 | length 29.6
  Top Layer w0.152: v2(19.403,24.915) 20.34,23.978 32.007,23.978 33.099,25.07 R49.1@33.985,25.07
  G1 w0.152: v2(10.147,28.788) 12.078,30.719 16.58,30.719 19.403,27.895 v2(19.403,24.915)
NetR50_2: R50.2 U9.4 | length 2.7
  Top Layer w0.152: R50.2@23.063,40.251 23.304,40.009 ; 23.381,39.958 24.845,38.494 U9.4@25.121,38.494
NetR51_2: R51.2 U9.3 | length 3.2
  Top Layer w0.152: U9.3@26.467,38.494 26.742,38.494 28.482,40.234 28.677,40.234 R51.2@28.854,40.411
NetR53_1: R53.1 U7.G1 | length 27.2
  Top Layer w0.152: U7.G1@13.15,28.788 17.566,28.788 18.24,28.115 18.24,27.747 17.94,27.447 17.94,24.318 19.568,22.69 32.314,22.69 32.495,22.508 32.495,21.558 32.794,21.26 R53.1@33.985,21.26
NetR54_2: R54.2 R55.2 U7.F2 | length 27.4
  Top Layer w0.152: v2(12.649,28.288) U7.F2@12.683,28.288 ; v2(15.189,28.143) R55.2@15.824,28.143 ; v2(17.422,24.112) 19.149,22.385 31.628,22.385 32.131,21.882 32.131,20.348 32.464,20.015 R54.2@33.985,20.015
  G2 w0.102: v2(15.189,28.143) 15.189,26.345 v2(17.422,24.112)
  Bottom Layer w0.102: v2(12.649,28.288) 15.044,28.288 v2(15.189,28.143)
NetR55_1: R55.1 U7.G2 | length 6.1
  Top Layer w0.152: R55.1@17.094,28.143 v2(17.78,28.143)
  Bottom Layer w0.102: v2(12.675,28.804) 17.12,28.804
  Bottom Layer w0.152: 17.12,28.804 v2(17.78,28.143)
NetR56_2: R56.2 U7.F4 | length 30.4
  Top Layer w0.152: v2(17.625,27.445) 17.625,25.883 17.079,25.336 17.079,23.673 19.233,21.519 31.557,21.519 31.557,19.555 32.367,18.745 R56.2@33.985,18.745
  Bottom Layer w0.102: v2(11.648,28.288) 12.09,27.846 14.782,27.846
  Bottom Layer w0.152: 14.782,27.846 14.79,27.838 17.231,27.838 v2(17.625,27.445)
NetR59_1: R59.1 U7.D2 | length 27.8
  Top Layer w0.152: R59.1@35.255,26.365 v2(36.114,26.365)
  G1 w0.152: v2(28.41,25.517) 28.425,25.502 28.425,24.902 28.842,24.486 35.334,24.486 36.114,25.265 v2(36.114,26.365)
  Bottom Layer w0.102: v2(12.649,27.287) 13.288,27.287 13.372,27.371 13.603,27.371 13.687,27.287 14.622,27.287
  Bottom Layer w0.152: 14.622,27.287 14.909,27 27.724,27 28.41,26.314 v2(28.41,25.517)
NetR60_1: R60.1 U7.D3 | length 5.7
  Top Layer w0.152: R60.1@17.018,26.848 v2(17.018,27.432)
  Top Layer w0.254: R60.1@17.018,26.848 R60.1@17.069,26.797
  Bottom Layer w0.102: v2(12.141,27.28) 12.454,27.592 14.677,27.592
  Bottom Layer w0.152: 14.677,27.592 14.837,27.432 v2(17.018,27.432)
NetR61_2: R61.2 U7.F3 | length 11.3
  Top Layer w0.152: R61.2@20.726,31.445 20.93,31.242 v2(20.93,30.836)
  Bottom Layer w0.102: v2(12.149,28.288) 12.149,29.599 13.36,30.81
  Bottom Layer w0.152: 13.36,30.81 13.386,30.836 v2(20.93,30.836)
NRST: R52.2 R57.1 U7.C7 | length 4.8
  Top Layer w0.152: v2(9.347,24.511) 9.5,24.359 9.5,23.467 9.505,23.472 R57.1@10.546,23.472
  Bottom Layer w0.102: v2(9.347,24.511) 9.347,25.987 v2@10.14,26.779
  Bottom Layer w0.152: v2@10.14,26.779 v2@10.147,26.779
  other v2: 10.16,26.772
OSC_IN: C27.1 R44.2 U7.D8 X1.2 | length 10.6
  Top Layer w0.152: R44.2@7.239,26.721 7.976,26.721 8.541,27.286 9.646,27.286 U7.D8@9.647,27.287
  Top Layer w0.254: C27.1@3.607,21.209 X1.2@3.607,24.689 5.639,26.721 R44.2@7.239,26.721
OSC_OUT: C28.1 R44.1 U7.D7 X1.1 | length 11.5
  Top Layer w0.152: R44.1@7.239,27.991 7.264,27.965 v2(7.925,27.965)
  Top Layer w0.254: C28.1@3.607,33.706 X1.1@3.607,29.769 5.385,27.991 R44.1@7.239,27.991
  Bottom Layer w0.102: v2(7.925,27.965) 8.687,27.965 9.307,27.346 9.342,27.381 9.393,27.33 v2(10.135,27.33)
PA0: R16.1 R33.1 U1.F6 | length 57.6
  Top Layer w0.102: v2@33.96,35.243 33.978,35.262 R33.1@33.978,36.003 ; v2(56.541,43.802) 57.655,43.802 57.964,43.492 58.534,43.492 R16.1@58.54,43.499
  G2 w0.102: v2@56.546,43.817 56.852,43.51 63.92,43.51 64.309,43.121 64.309,42.626 62.796,41.112 62.796,37.587 63.195,37.188 63.195,34.35 63.199,34.354 63.199,32.926 65.78,30.345 65.78,26.744 65.398,26.362 64.402,26.362 v3@64.31,26.27
  Bottom Layer w0.152: v2(33.971,35.239) 34.444,35.239 39.731,40.526 40.593,40.526 40.856,40.263 41.05,40.263 43.613,42.827 43.613,43.465 43.915,43.767 48.391,43.767 48.425,43.801 v2@56.534,43.801
  other v3: 64.28,26.244
PA1: R13.1 R35.1 U1.G6 | length 50.7
  Top Layer w0.102: v2@63.048,40.28 63.092,40.236 63.092,36.85 65.051,34.891 65.051,33.768 65.353,33.466 65.353,32.47 66.017,31.806 66.017,29.663 66.016,29.662 66.016,27.626 U1.G6@64.615,26.226
  Top Layer w0.152: R35.1@37.032,34.293 37.032,33.577 37.306,33.303 50.59,33.303 56.01,38.722 v2(56.01,42.664) 56.01,43.457 R13.1@55.994,43.472
  Bottom Layer w0.102: v2(56.01,42.664) 56.633,42.664 57.461,41.836 61.617,41.836 63.014,40.44 63.014,40.412 63.065,40.361 v2@63.065,40.336
  other v2: 63.076,40.31
PA4: R12.1 U1.E3 | length 31.5
  Top Layer w0.152: R12.1@50.876,43.497 50.881,43.492 v2(50.881,42.855)
  G2 w0.102: v3@63.806,25.016 63.806,25.04 63.856,25.091 63.856,25.111 64.01,25.265 64.01,25.311 ; 64.01,25.309 64.01,25.52 64.124,25.634 64.324,25.634 64.353,25.664 64.49,25.664 64.553,25.6 65.631,25.6 66.612,26.581 66.612,32.456 66.393,32.675 66.393,32.681 66.115,32.958 66.113,32.958 65.769,33.303 65.766,33.303 64.436,34.633 v2@64.436,35.938
  Bottom Layer w0.152: v2(50.881,42.855) 50.881,42.047 52.713,40.216 54.076,40.216 58.334,35.958 v2@64.44,35.958
  other v2: 64.433,35.975
  other v3: 63.806,25.012
PA5: R11.1 R40.2 U1.F5 | length 62.1
  Top Layer w0.152: R40.2@31.064,31.547 45.842,31.547 v2@45.844,31.549 ; R11.1@46.863,43.497 46.876,43.485 v2(46.876,42.72)
  G2 w0.102: v3(64.214,25.904) 64.221,25.904 64.241,25.884 64.325,25.968 64.412,25.968 64.554,26.11 64.802,26.11 64.905,26.007 65.355,26.007 65.991,26.643 65.991,30.708 v2@64.727,31.973
  Bottom Layer w0.152: v2(45.832,31.556) 45.832,36.909 46.147,37.225 46.147,37.815 43.971,39.991 43.971,41.02 44.865,41.914 46.859,41.914 46.866,41.921 ; 46.865,41.53 46.865,39.742 46.796,39.673 46.787,39.673 46.599,39.484 46.599,39.232 46.777,39.053 47.03,39.053 47.04,39.063 48.082,39.063 52.66,34.486 52.66,34.483 53.052,34.09 53.062,34.09 54.576,32.576 64.102,32.576 64.712,31.966 v2(64.712,31.973) ; 46.876,41.549 v2(46.876,42.72)
PA7: R14.1 U1.G5 | length 27
  Top Layer w0.152: v2(53.429,39.911) 53.429,43.472 R14.1@53.454,43.497
  G2 w0.102: v3(64.658,25.854) 64.709,25.804 65.519,25.804 66.194,26.479 66.194,32.015 v2@66.174,32.036
  Bottom Layer w0.152: v2(53.429,39.911) 53.975,39.365 54.568,39.365 60.704,33.229 62.02,33.229 62.021,33.228 65.009,33.228 v2@66.194,32.042
  other v2: 66.188,32.03
PA8: R24.1 R48.1 U1.E7 | length 107.2
  Top Layer w0.102: v2@47.823,16.57 47.823,18.964 49.875,21.016 49.875,27.514 52.546,30.185 60.858,30.185 63.827,27.217 63.827,26.623 U1.E7@63.826,26.621
  Top Layer w0.152: R48.1@35.255,23.825 37.744,23.825 47.447,14.122 v2(54.966,14.122) ; R24.1@68.694,43.485 68.704,43.475 v2(68.704,42.642)
  Bottom Layer w0.152: v2@47.794,16.553 47.794,15.924 49.596,14.122 v2(54.966,14.122) 54.978,14.11 62.471,14.11 v2(62.484,14.097) 65.235,14.097 65.252,14.08 69.337,14.08 69.866,14.609 69.866,14.632 70.956,15.723 70.962,15.723 71.704,16.465 71.704,16.47 72.001,16.767 72.001,24.297 72.012,24.307 72.012,25.007 72.001,25.018 72.001,27.199 70.572,28.629 70.572,31.89 ; v2(68.704,42.642) 70.572,40.774 70.572,35.823 ; 70.572,32.486 70.572,33.009 70.569,33.011 70.569,33.525 70.572,33.527 70.572,34.166 ; 70.572,34.723 70.572,35.304 ; 70.572,31.89 70.572,32.485 ; 70.572,34.166 70.572,34.723 ; 70.572,35.305 70.572,35.822
  other v2: 47.805,16.567
PA9: R22.1 R49.2 U1.D7 | length 100
  Top Layer w0.102: 48.284,14.91 48.335,14.961 48.335,19.085 50.114,20.865 50.114,27.373 52.7,29.959 55.359,29.959 55.361,29.957 60.752,29.957 63.407,27.302 63.407,26.63 U1.D7@63.416,26.621
  Top Layer w0.152: R49.2@35.255,25.07 37.973,25.07 48.133,14.91 v2(54.864,14.91) ; R22.1@66.142,43.485 66.154,43.472 v2(66.154,42.634)
  Bottom Layer w0.152: v2(54.864,14.91) 54.877,14.896 v2(61.837,14.896) 61.846,14.905 63.8,14.905 63.839,14.944 65.609,14.944 65.626,14.927 67.267,14.927 67.284,14.944 67.848,14.944 68.178,14.613 69.202,14.613 70.841,16.252 70.841,16.262 71.164,16.586 71.175,16.586 71.744,17.155 71.744,24.398 71.739,24.403 71.739,24.905 71.733,24.911 71.733,27.108 70.318,28.523 70.318,31.995 ; v2(66.154,42.634) 70.318,38.471 70.318,35.717 ; 70.318,32.38 70.318,32.904 70.315,32.906 70.315,33.63 70.318,33.632 70.318,34.271 ; 70.318,34.618 70.318,35.409 ; 70.318,31.995 70.318,32.38 ; 70.318,34.271 70.318,34.617 ; 70.318,35.41 70.318,35.717
PA10: C40.2 R31.1 R47.1 R62.2 SW2.1 SW2.2 U1.E6 | length 111.8
  Top Layer w0.102: C40.2@14.351,12.852 C40.2@14.402,12.802 ; v2(14.961,12.802) v2@14.986,12.827 ; v2(33.123,11.259) 33.128,11.255 R62.2@33.128,10.375
  Top Layer w0.152: C40.2@14.402,12.802 v2(14.961,12.802) ; v2@14.986,12.827 R31.1@15.57,12.827 ; R47.1@35.255,22.555 37.668,22.555 v2(47.015,13.208)
  Top Layer w0.254: SW2.1@12.513,1.107 SW2.2@12.513,9.117 12.513,10.43 14.351,12.268 C40.2@14.351,12.852
  G2 w0.102: v2@61.247,13.163 61.247,13.635 v2(63.254,15.641) ; v3@63.804,26.234 63.804,26.431 ; 63.805,26.431 v2@63.805,30.351
  Bottom Layer w0.102: v2(33.123,11.259) 33.123,13.203 33.128,13.208 33.131,13.211 ; v2@63.261,15.649 63.253,15.657 63.457,15.861 68.477,15.861 69.172,16.556 69.172,27.007 65.852,30.328 v2(63.813,30.328)
  Bottom Layer w0.152: v2(14.961,12.802) 14.961,13.843 16.231,15.113 23.896,15.113 25.801,13.208 33.128,13.208 v2(47.015,13.208) 61.214,13.208 v2(61.265,13.157)
  other v3: 63.772,26.223
PA11: R1.1 U1.D3 U7.H7 | length 78.6
  Top Layer w0.152: U7.H7@10.142,29.289 10.147,29.294 10.147,30.213 10.602,30.668 13.091,30.668 15.535,33.111 16.896,33.111 17.993,34.209 17.993,38.369 23.256,43.632 23.868,43.632 R1.1@24.003,43.497
  G2 w0.152: v2(18.004,35.06) 18.591,35.06 28.105,25.546 28.105,25.337 32.38,21.062 v2(32.38,19.52)
  Bottom Layer w0.102: 49.83,19.285 49.833,19.288 52.707,19.288 52.708,19.29 57.175,19.29 61.112,23.227 61.112,23.777 62.006,24.671 62.319,24.671 62.463,24.816 62.491,24.816 62.496,24.811 62.725,24.811 62.736,24.822 63.142,24.822 63.238,24.919 63.327,25.007 v3@63.43,25.007
  Bottom Layer w0.152: v2(32.38,19.52) 33.222,19.52 33.517,19.225 49.374,19.225 49.434,19.285 49.83,19.285 ; v3@63.43,25.007 v3(63.44,25.017)
PA12: R21.2 U1.D6 | length 39.5
  Top Layer w0.102: R21.2@63.601,9.725 R21.2@63.627,9.751 ; v2@63.619,10.539 63.627,10.531 R21.2@63.627,9.751 ; R21.2@63.627,9.703 R21.2@63.627,9.751
  G2 w0.102: v2@63.423,30.711 63.524,30.61 63.524,26.536 63.463,26.475 63.463,26.226 v3(63.467,26.221) ; v2(63.637,10.539) 62.647,10.539 62.054,9.947 60.842,9.947 60.735,10.055 60.735,11.364 62.592,13.222 62.592,13.224 63.697,14.328 v2@63.697,15.441
  Bottom Layer w0.102: v2(63.436,30.718) 63.546,30.607 65.869,30.607 69.008,27.468 69.008,27.465 69.401,27.072 69.401,16.333 68.618,15.55 63.795,15.55 v2@63.712,15.467
  other v2: 63.688,15.468
PA13: R4.1 R18.1 R38.2 U1.D5 U7.E5 | length 104.4
  Top Layer w0.152: R4.1@34.163,43.497 34.284,43.619 34.769,43.619 v2(34.986,43.835) ; R38.2@46.92,40.978 46.971,41.028 47.675,41.028 48.265,41.618 v2(48.265,44.072) ; v2(61.074,42.669) R18.1@61.074,43.472
  G1 w0.102: v2(11.148,27.788) 11.148,26.698 12.611,25.235 v2(12.611,22.509)
  G2 w0.102: 60.257,41.13 60.234,41.106 60.234,32.868 63.22,29.882 63.22,29.443 63.221,28.405 63.22,28.404 63.22,26.421 63.219,26.333 63.213,26.327 63.213,26.081 v3(63.454,25.84) ; 60.263,41.134 61.061,41.932 61.061,42.626 v2@61.095,42.66
  G2 w0.152: v2(11.148,27.788) v2@11.153,27.783
  Bottom Layer w0.152: v2@12.597,22.511 13.425,23.34 21.577,23.34 21.628,23.289 26.613,23.289 28.715,25.391 28.715,26.369 27.639,27.444 27.639,40.317 27.428,40.528 25.998,40.528 25.222,41.304 25.222,42.913 26.053,43.744 27.637,43.744 27.729,43.835 v2(34.986,43.835) 35.222,44.072 v2(48.265,44.072) ; v2@48.265,44.077 48.367,44.179 56.601,44.179 58.11,42.669 v2(61.074,42.669)
PA14: R6.1 R41.1 U1.C7 U7.G5 | length 104.9
  Top Layer w0.102: v2@49.625,19.88 50.373,20.628 50.373,27.344 52.784,29.756 55.275,29.756 55.277,29.754 60.668,29.754 63.01,27.411 U1.C7@63.01,26.621
  Top Layer w0.152: R6.1@36.703,43.497 36.703,42.888 37.272,42.319 38.435,42.319 39.669,41.085 39.669,40.582 40.041,40.21 v2@40.453,40.21 ; v2(40.456,40.206) 41.198,40.206 R41.1@41.212,40.192
  G2 w0.152: v2(11.148,28.788) 11.148,29.723 11.717,30.292 13.167,30.292 13.35,30.109 14.696,30.109 15.037,29.769 15.037,28.422 14.884,28.269 14.884,28.017 14.915,27.986 v2@14.915,22.931 ; v2(40.456,40.206) 40.549,40.206 42.402,38.352 42.402,35.933 42.804,35.531 45.223,35.531 46.185,34.57 46.185,27.467 45.242,26.525 45.242,23.244 48.606,19.88 v2(49.642,19.88)
  Bottom Layer w0.152: v2(14.91,22.921) 30.848,22.921 33.889,19.88 v2(49.642,19.88)
PA15: R7.1 R37.2 U1.C6 U7.G4 | length 78.4
  Top Layer w0.102: R37.2@43.065,41.659 43.87,40.854 v2(44.636,40.854)
  Top Layer w0.152: v2(23.671,42.203) 23.679,42.211 26.008,42.211 v2(26.017,42.202) ; v2(39.233,42.692) 39.233,43.487 R7.1@39.243,43.497
  G2 w0.102: v2@61.713,30.614 61.714,30.612 62.043,30.612 62.959,29.696 v3(62.959,26.234)
  G2 w0.152: v2(39.233,42.692) 40.474,43.934 43.9,43.934 45.017,42.816 45.017,41.218 v2@44.636,40.837
  Bottom Layer w0.102: v2@11.648,28.798 11.895,29.045 11.895,30.488 13.36,31.953 ; v2@44.651,40.856 47.671,37.836 48.706,37.836 49.393,37.149 ; 49.393,37.148 51.611,34.93 51.613,34.93 55.912,30.631 v2@61.732,30.631
  Bottom Layer w0.152: v2(11.648,28.788) v2@11.648,28.798 ; 13.36,31.953 21.392,31.953 21.763,32.324 21.763,34.458 21.031,35.189 21.031,36.581 23.68,39.23 23.68,42.185 v2@23.669,42.196 ; v2(26.017,42.202) 26.017,42.989 26.264,43.236 27.267,43.236 27.81,42.692 v2(39.233,42.692)
  other v2: 61.717,30.621
PB0: R20.1 R42.1 U1.C5 | length 53.9
  Top Layer w0.152: v2(40.305,36.107) 41.256,36.107 R42.1@41.257,36.106 ; R20.1@63.627,43.497 63.635,43.49 v2(63.635,42.741)
  G2 w0.102: 59.754,42.149 58.632,41.027 58.632,28.614 61.632,25.614 62.492,25.614 62.501,25.624 62.731,25.624 v3(62.946,25.839) ; 59.757,42.149 60.711,43.103 63.337,43.103 63.571,42.869 63.571,42.845 63.634,42.783 v2@63.634,42.752
  Bottom Layer w0.152: v2(40.305,36.107) 40.57,36.373 40.57,38.124 41.69,39.243 41.717,39.243 45.857,43.383 56.398,43.383 57.556,42.225 61.703,42.225 62.218,42.741 v2(63.635,42.741)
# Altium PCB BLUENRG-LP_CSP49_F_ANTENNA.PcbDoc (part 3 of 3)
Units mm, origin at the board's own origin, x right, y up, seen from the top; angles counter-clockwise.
Board outline 90.84 x 54.03 mm, 4 copper layers (Top Layer, G1, G2, Bottom Layer), stack 1.697 mm thick; 159 components, 123 nets, 503 pads, 685 vias.

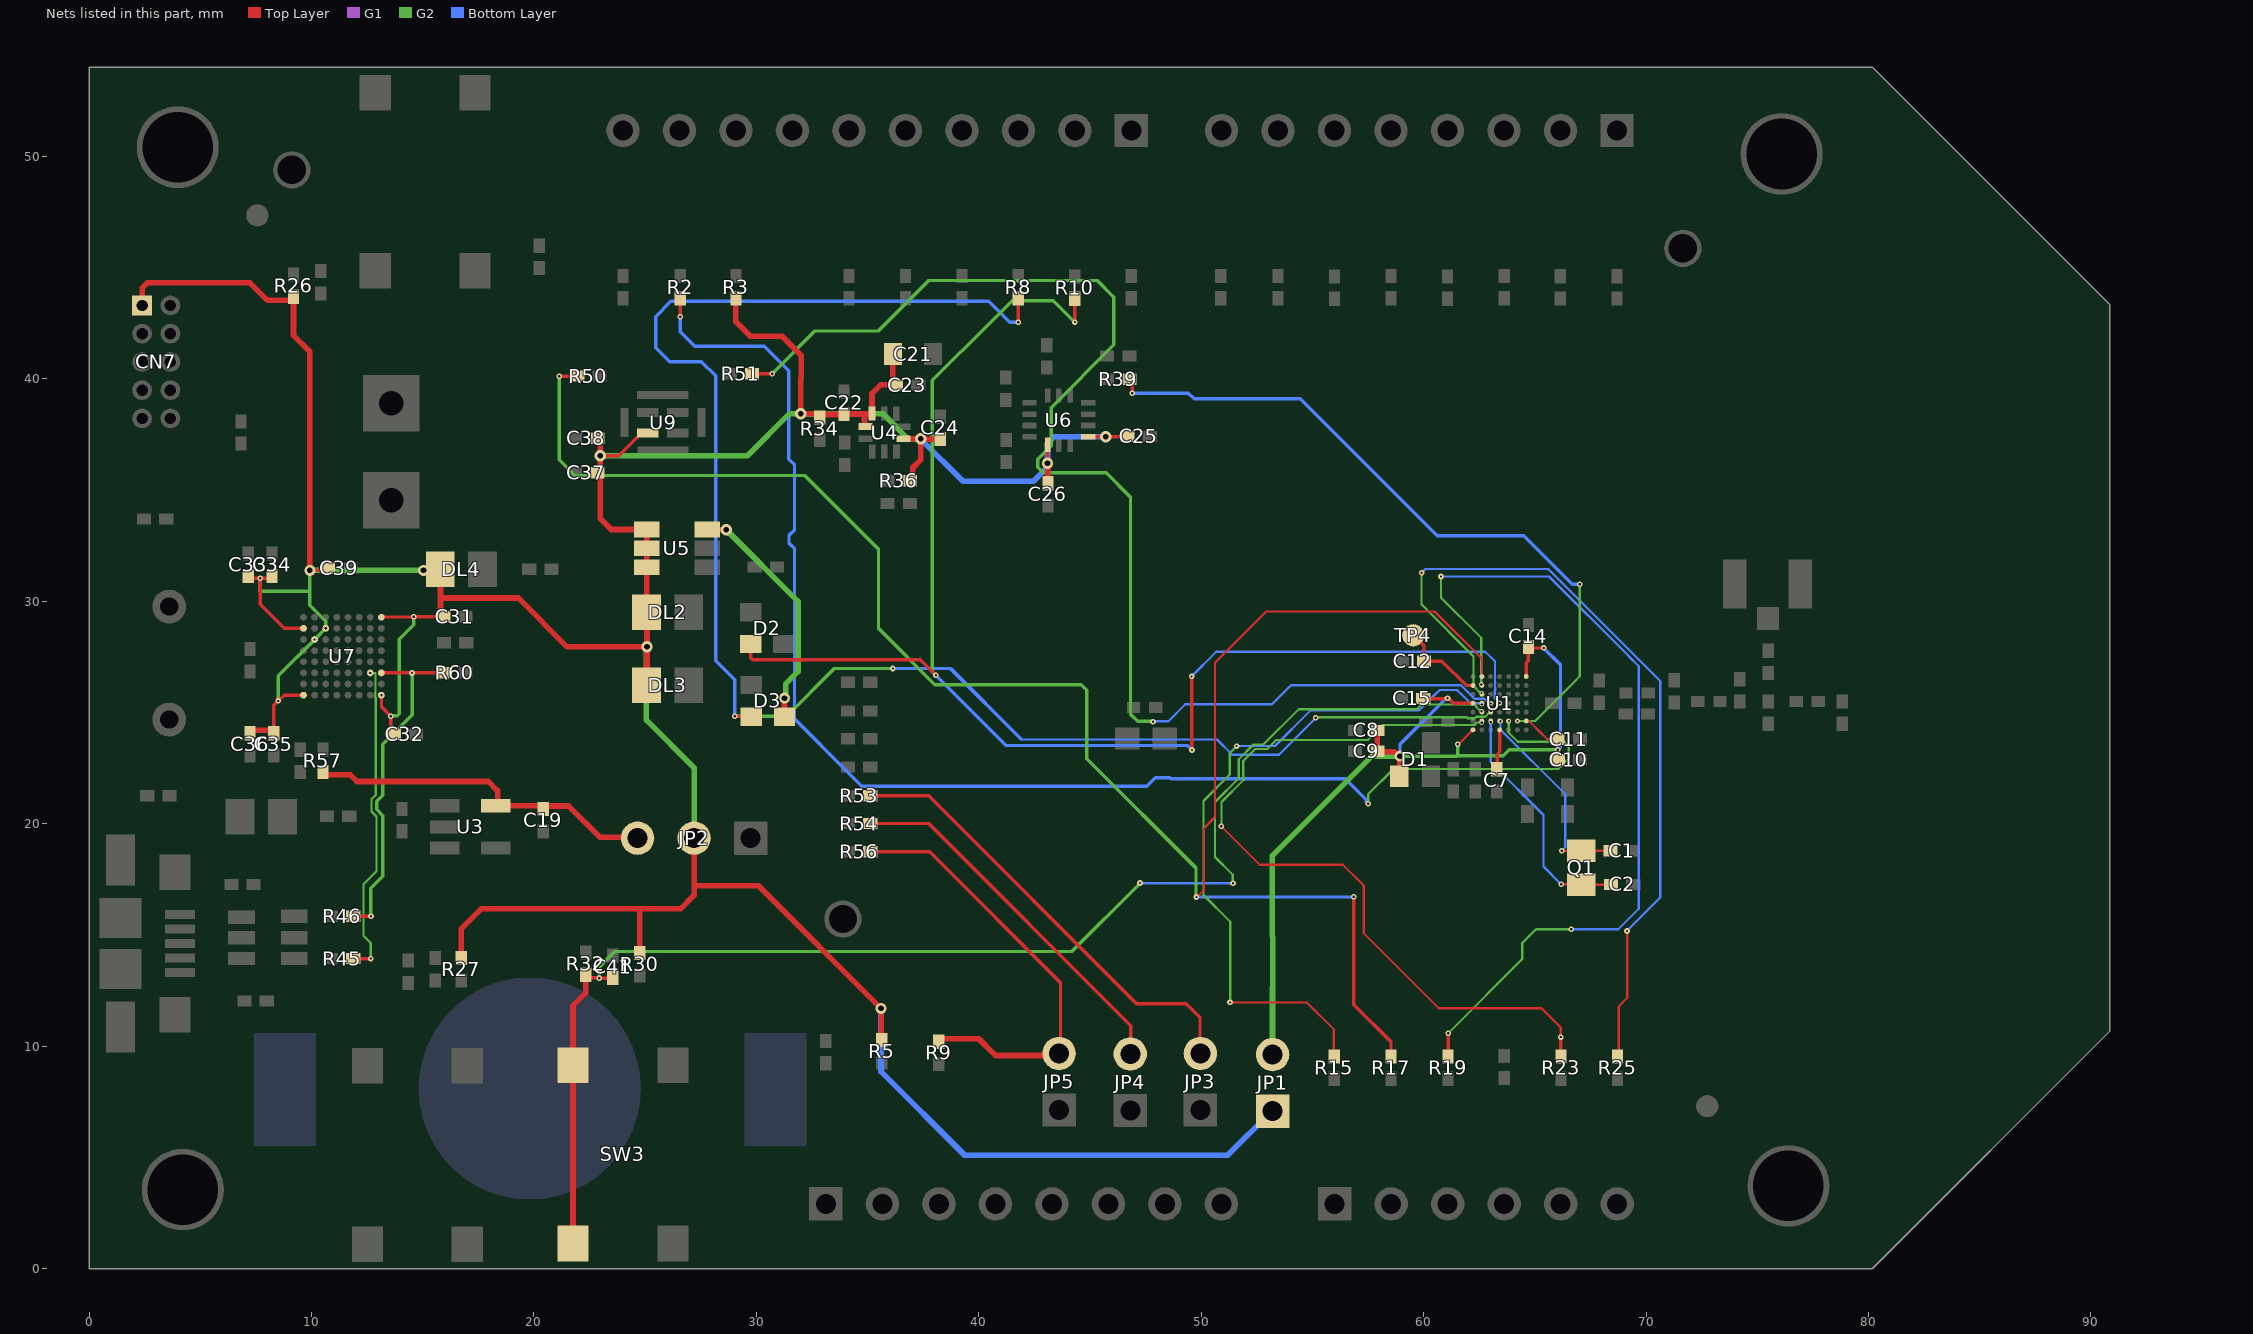
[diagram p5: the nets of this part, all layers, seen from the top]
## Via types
v1: diameter 0.508, hole 0.254, Top Layer to Bottom Layer, tented both sides, 522 vias
v2: diameter 0.254, hole 0.102, Top Layer to Bottom Layer, tented both sides, 133 vias
v3: diameter 0.203, hole 0.102, Top Layer to Bottom Layer, tented both sides, 30 vias

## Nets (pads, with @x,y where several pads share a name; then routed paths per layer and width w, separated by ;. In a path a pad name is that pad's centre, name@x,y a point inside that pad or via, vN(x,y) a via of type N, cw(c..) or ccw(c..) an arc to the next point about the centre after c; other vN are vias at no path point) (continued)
PB1: R51.1 U1.C4 | length 59.1
  Top Layer w0.152: R51.1@29.947,40.234 29.952,40.239 v2(30.711,40.239)
  G2 w0.152: v2@30.687,40.21 32.634,42.158 35.474,42.158 37.745,44.429 45.329,44.429 46.078,43.679 46.078,41.529 43.262,38.713 43.262,37.002 42.656,36.396 42.656,36.038 42.909,35.785 45.731,35.785 46.824,34.692 46.824,24.936 47.151,24.609 v2@47.822,24.609
  Bottom Layer w0.102: v2@47.819,24.618 48.527,24.618 49.287,25.378 53.181,25.378 54.035,26.233 61.676,26.233 62.287,25.621 62.432,25.621 62.434,25.624 62.727,25.624 62.916,25.435 63.02,25.435 v3@63.034,25.42 ; v3@63.028,25.415 v3(63.03,25.415)
  other v2: 47.833,24.594
PB2: R17.2 R50.1 U1.B7 | length 86.2
  Top Layer w0.102: v2@49.776,16.764 49.873,16.764 50.125,17.017 50.125,17.297 50.124,17.299 50.124,19.807 50.621,20.305 50.621,27.244 52.928,29.55 60.492,29.55 62.62,27.422 U1.B7@62.62,26.621
  Top Layer w0.152: v2(21.138,40.127) R50.1@21.814,40.127 ; v2(56.857,16.726) 56.857,11.876 58.534,10.198 R17.2@58.534,9.677
  Top Layer w0.254: R50.1@21.814,40.127 R50.1@21.819,40.132
  G2 w0.152: v2(21.138,40.127) 21.138,36.368 21.844,35.662 32.181,35.662 35.494,32.349 35.494,28.786 38.026,26.253 44.601,26.253 44.854,26 44.854,22.929 49.767,18.015 49.767,16.774 49.787,16.755 v2(49.787,16.71)
  Bottom Layer w0.152: v2(49.787,16.71) 56.84,16.709 v2(56.857,16.726)
PB3: R19.2 U1.B6 | length 39.2
  Top Layer w0.152: R19.2@61.1,9.677 61.112,9.69 v2(61.112,10.592)
  G2 w0.102: v2@60.78,31.139 v2(60.78,31.121) 60.78,30.169 62.586,28.363 62.586,26.278 v3(62.595,26.269) ; v2@61.147,10.633 64.439,13.924 64.439,14.645 65.056,15.263 v2@66.64,15.263
  Bottom Layer w0.102: v2(60.78,31.121) 65.643,31.121 69.211,27.553 69.211,27.55 69.675,27.086 69.675,16.184 68.754,15.263 v2@66.657,15.263
  other v2: 66.639,15.257
PB4: R25.2 U1.B5 | length 36.9
  Top Layer w0.102: R25.2@68.772,9.739 68.772,11.793 69.159,12.18 v2@69.159,15.176
  G2 w0.102: v2@59.902,31.286 59.902,29.875 62.248,27.529 62.248,26.247 ; 62.245,26.243 62.245,26.189 62.34,26.094 62.58,25.854 62.6,25.835 62.614,25.849 62.604,25.859 v3(62.604,25.878)
  Bottom Layer w0.102: v2(59.911,31.286) 60.08,31.456 65.606,31.456 70.64,26.422 70.64,16.693 v2@69.162,15.215
  other v2: 69.145,15.183
PB5: R15.2 U1.B4 | length 31.3
  Top Layer w0.102: v2(51.294,11.973) 54.751,11.973 55.961,10.764 R15.2@55.961,9.681
  G2 w0.102: v2@51.302,11.966 51.302,15.598 50.101,16.799 50.101,21.032 51.283,22.214 51.283,23.186 51.543,23.446 51.604,23.446 v2@51.621,23.43
  Bottom Layer w0.102: v2@51.582,23.507 51.592,23.497 53.317,23.497 54.929,25.109 59.805,25.109 60.556,25.861 60.572,25.861 60.728,26.017 61.501,26.017 61.673,25.845 61.676,25.845 62.103,25.418 62.516,25.418 62.518,25.421 62.568,25.421 v3(62.618,25.37)
  other v2: 51.593,23.496
PB6: C41.2 R32.1 SW3.1 SW3.2 U1.B3 | length 62.5
  Top Layer w0.102: v2@22.911,13.081 v2(22.936,13.056) ; C41.2@23.52,13.056 C41.2@23.546,13.081
  Top Layer w0.152: R32.1@22.327,13.081 v2@22.911,13.081 ; v2(22.936,13.056) C41.2@23.52,13.056
  Top Layer w0.254: SW3.1@21.759,1.132 SW3.2@21.759,9.142 21.759,11.827 22.327,12.395 R32.1@22.327,13.081
  G2 w0.102: v2@51.423,17.344 51.423,17.708 50.621,18.509 50.621,20.978 51.689,22.045 51.689,22.909 52.348,23.569 52.794,23.569 54.382,25.156 56.603,25.156 56.605,25.154 58.73,25.154 58.732,25.156 59.703,25.156 59.909,25.362 61.19,25.362 61.198,25.37 62.285,25.37 62.362,25.293 62.362,25.265 62.557,25.07 v3@62.601,25.07 ; v3(62.604,25.065) v3(62.604,25.065) v3@62.601,25.07 ; v3@62.601,25.07 62.601,25.079 62.603,25.081 62.615,25.07 v3@62.601,25.07
  G2 w0.152: v2(22.936,13.056) 22.936,13.564 23.635,14.262 44.176,14.262 v2(47.252,17.338)
  Bottom Layer w0.102: v2@47.243,17.345 47.254,17.334 v2(51.429,17.334)
PB7: R23.2 U1.B2 | length 36.2
  Top Layer w0.102: v2@50.909,19.903 v2(50.901,19.894) v2(50.901,19.894) 52.629,18.167 56.369,18.167 57.308,17.228 57.308,15.082 60.681,11.709 65.303,11.709 66.167,10.846 v2(66.167,10.414)
  Top Layer w0.152: v2(66.167,10.414) 66.167,9.69 R23.2@66.18,9.677
  G2 w0.102: v2@50.915,19.945 50.915,20.984 51.892,21.961 51.892,22.825 52.433,23.365 52.968,23.365 53.372,23.77 57.491,23.77 58.169,24.448 62.29,24.448 62.395,24.553 62.566,24.553 v3@62.598,24.586
  other v3: 62.615,24.545
PB8: D2.1 R10.1 U1.D4 | length 64.3
  Top Layer w0.152: D2.1@29.743,28.092 29.743,27.463 29.832,27.374 37.379,27.374 v2(38.074,26.678) ; v2(44.323,42.558) R10.1@44.323,43.472 ; v2@49.57,26.617 49.585,26.602 v2(49.585,23.318)
  G2 w0.152: v2(38.074,26.678) 37.909,26.843 37.909,39.934 40.533,42.558 ; 40.533,42.558 41.5,43.526 42.316,43.526 ; 42.317,43.525 43.356,43.525 v2(44.323,42.558)
  Bottom Layer w0.102: v2@49.566,26.625 v2(49.57,26.629) 50.679,27.737 56.085,27.737 56.087,27.739 62.774,27.739 63.207,27.307 63.207,26.352 63.219,26.34 63.219,26.333 63.213,26.327 63.213,26.116 63.219,26.11 63.219,26.005 63.2,25.986 63.2,25.651 v3(63.421,25.43)
  Bottom Layer w0.152: v2(38.074,26.678) 41.232,23.521 49.39,23.521 v2@49.589,23.321
PB9: D3.1 R8.1 U1.C3 | length 76.3
  Top Layer w0.152: v2(29.032,24.841) D3.1@29.743,24.841 ; v2@41.783,42.553 R8.1@41.783,43.497
  Top Layer w0.254: D3.1@29.743,24.841 D3.1@29.769,24.816 ; v2(41.775,42.545) v2@41.783,42.553
  G2 w0.102: v2@55.157,24.767 55.185,24.795 55.281,24.795 55.283,24.796 61.941,24.796 61.989,24.749 62.295,24.749 62.362,24.816 62.491,24.816 ; 62.505,24.811 62.771,24.811 63.006,25.046 v3@63.016,25.046
  G2 w0.152: v2(29.032,24.841) 31.369,24.841 33.513,26.985 v2(36.142,26.985)
  Bottom Layer w0.102: 41.92,23.795 50.716,23.795 51.4,23.111 53.504,23.111 v2@55.153,24.76
  Bottom Layer w0.152: v2(29.032,24.841) 29.032,26.486 28.176,27.342 28.176,40.14 27.534,40.782 26.104,40.782 25.476,41.41 25.476,42.808 26.158,43.49 40.452,43.49 41.397,42.545 v2(41.775,42.545) ; v2(36.142,26.985) 38.73,26.985 41.92,23.795
  other v2: 55.147,24.766
  other v3: 63.018,25.076
PB12: C2.2 Q1.1 U1.C2 | length 10.8
  Top Layer w0.102: v2@66.218,17.279 67.074,17.279 Q1.1@67.087,17.266 68.385,17.266 C2.2@68.409,17.242
  Bottom Layer w0.102: v3(63.022,24.568) 63.022,22.772 65.391,20.403 65.391,18.081 v2@66.193,17.279
  other v2: 66.194,17.283
PB13: C1.2 Q1.2 U1.D2 | length 9.3
  Top Layer w0.102: v2@66.228,18.8 66.237,18.79 Q1.2@67.087,18.79 68.376,18.79 C1.2@68.393,18.807
  Bottom Layer w0.102: v3(63.458,24.613) 63.458,24.235 66.364,21.329 66.364,18.945 v2@66.214,18.795
  other v2: 66.213,18.797
PB14: R2.1 U1.E2 | length 64.7
  Top Layer w0.152: v2(26.576,42.794) 26.576,43.492 R2.1@26.581,43.497
  G2 w0.102: v2@57.506,20.883 v2@57.528,20.905 ; v2@57.517,20.941 57.517,21.341 58.647,22.471 66.042,22.471 66.528,22.958 66.528,23.489 66.328,23.689 64.234,23.689 63.83,24.093 v3@63.83,24.628
  Bottom Layer w0.152: v2(26.576,42.794) 26.576,42.131 27.239,41.468 30.358,41.468 31.463,40.363 31.463,36.401 31.72,36.144 31.72,33.228 31.471,32.979 31.471,32.621 31.72,32.372 31.72,24.714 34.063,22.37 34.063,22.365 34.744,21.684 47.556,21.684 47.945,22.073 48.591,22.073 48.64,22.024 51.306,22.024 51.309,22.02 52.034,22.02 52.036,22.022 56.482,22.022 57.418,21.086 v2@57.418,20.977
  other v2: 57.509,20.908
  other v3: 63.836,24.628
PB15: R39.2 U1.F2 | length 32.1
  Top Layer w0.152: R39.2@46.897,40.026 46.903,40.019 v2(46.903,39.358)
  G2 w0.102: v3(64.216,24.626) 65.014,24.626 66.758,26.37 ; 66.758,26.371 67.024,26.636 67.024,27.36 67.022,27.362 v2(67.023,30.767)
  Bottom Layer w0.152: v2(46.903,39.358) 49.417,39.358 49.428,39.368 49.685,39.111 54.463,39.111 60.613,32.96 64.501,32.96 66.692,30.769 v2@67.027,30.769
RED: D3.3 U5.6 | length 10.9
  Top Layer w0.152: U5.6@27.79,33.235 U5.6@27.802,33.223
  Top Layer w0.254: U5.6@27.802,33.223 v1(28.651,33.223) ; D3.3@31.267,24.816 v1(31.267,25.654)
  G2 w0.254: v1(28.651,33.223) 31.877,29.997 31.877,26.848 31.316,26.287 31.316,25.703 v1(31.267,25.654)
RSTN: JP5.2 R9.2 R56.1 | length 19.9
  Top Layer w0.152: R56.1@35.255,18.745 37.795,18.745 43.675,12.865 JP5.2@43.675,9.588
  Top Layer w0.254: R9.2@38.202,10.338 40.002,10.338 40.752,9.588 JP5.2@43.675,9.588
SWCLK: JP3.2 R53.2 | length 20.5
  Top Layer w0.152: R53.2@35.255,21.26 37.744,21.26 47.092,11.913 49.327,11.913 49.949,11.29 JP3.2@49.949,9.614
  G1 w0.254: JP3.2@49.936,9.614 JP3.2@49.949,9.614
SWDIO: JP4.2 R54.1 | length 16.7
  Top Layer w0.152: R54.1@35.255,20.015 37.744,20.015 46.838,10.922 JP4.2@46.838,9.576
USBDM: R46.1 R60.2 U7.C1 | length 15.3
  Top Layer w0.102: v2@14.521,26.787 v2(14.524,26.784) v2@14.536,26.797
  Top Layer w0.152: R46.1@12.014,15.85 12.017,15.847 v2(12.675,15.847) ; U7.C1@13.144,26.787 v2@14.521,26.787 ; v2@14.536,26.797 R60.2@15.799,26.797 ; R60.2@15.921,26.792 R60.2@15.926,26.797
  G2 w0.152: v2(12.675,15.847) 12.675,17.104 13.208,17.638 13.208,20.37 12.929,20.649 12.929,21.007 13.208,21.286 13.208,23.589 14.524,24.905 v2(14.524,26.784)
USBDP: R45.1 U7.C2 | length 14.3
  Top Layer w0.152: R45.1@12.014,13.945 12.017,13.942 v2(12.67,13.942)
  G2 w0.102: v2(12.644,26.787) 12.878,26.787 12.878,25.909 12.87,25.902 12.87,25.67 12.89,25.65 12.89,21.292 12.7,21.102 12.7,20.554 12.929,20.326 12.929,17.866 12.342,17.28 12.342,14.968 12.67,14.641 v2(12.67,13.942)
VCAP: C7.2 U1.D1 | length 1.8
  Top Layer w0.152: C7.2@63.302,22.44 63.302,23.116 63.418,23.232 U1.D1@63.418,24.211 ; U1.D1@63.418,24.212 U1.D1@63.418,24.226
VDD2: C8.2 C9.2 C10.2 C11.2 C14.2 C15.2 D1.3 JP1.2 U1.A1 U1.A4 U1.G2 U1.G7 | length 43.6
  Top Layer w0.102: v2(61.535,23.576) 61.571,23.576 U1.A1@62.21,24.216 ; U1.G2@64.626,24.617 64.754,24.617 65.282,24.089 ; 65.282,24.088 65.563,23.807 C11.2@66.027,23.807 ; C11.2@66.023,23.815 C11.2@66.034,23.804 ; C10.2@66.027,22.855 C10.2@66.031,22.852 ; v2@66.035,23.331 v2@66.038,23.334
  Top Layer w0.152: C15.2@59.97,25.542 60.049,25.621 v2@61.075,25.621 ; v2@61.075,25.633 v2@61.075,25.641 ; v2@61.142,25.629 61.346,25.425 62.207,25.425 62.212,25.43 U1.A4@62.218,25.43 ; U1.A1@62.211,24.216 U1.A1@62.224,24.228 ; U1.G7@64.615,26.626 64.615,27.246 64.696,27.327 C14.2@64.696,27.871 ; U1.G2@64.624,24.619 U1.G2@64.626,24.617 ; C14.2@64.714,27.943 64.753,27.904 v2@65.419,27.904 ; v2(66.034,23.334) C11.2@66.034,23.804 ; C10.2@66.035,22.878 v2@66.035,23.331
  Top Layer w0.254: C8.2@57.913,24.12 57.923,24.11 C9.2@57.923,23.265 ; C9.2@57.93,23.237 58.678,23.237 58.868,23.046 v1(58.937,23.046) 58.925,23.034 D1.3@58.925,22.142 ; C14.2@64.696,27.871 C14.2@64.735,27.911
  G2 w0.102: 61.519,23.178 61.53,23.178
  G2 w0.152: 53.207,12.643 53.211,12.646 ; v1(58.937,23.046) 61.505,23.046 61.53,23.071 ; v2@61.53,23.545 61.53,23.178 61.53,23.071 ; v2(66.034,23.334) 63.846,23.334 63.576,23.064 61.53,23.064 61.53,23.071
  G2 w0.254: 53.207,12.643 53.207,9.632 JP1.2@53.213,9.627 ; 53.211,12.646 53.211,14.913 53.191,14.933 53.191,18.56 57.677,23.046 58.553,23.046 v1(58.937,23.046)
  Bottom Layer w0.152: v1(58.937,23.046) 58.937,23.568 60.991,25.622 61.05,25.622 v2@61.085,25.657 ; v2@65.382,27.922 66.155,27.15 66.155,23.455 v2(66.034,23.334)
  other v2: 61.074,25.641 65.399,27.91
VDD_1: C21.2 C22.2 C23.2 C24.2 C25.2 C26.2 C31.2 C32.2 C33.2 C34.2 C35.2 C36.2 C37.2 C38.2 C39.2 CN7.1 DL2.1 DL3.1 DL4.1 JP1.1 JP2.2 R3.1 R5.2 R26.1 R27.1 R30.1 R34.1 R36.1 U4.1 U4.6 U4.10 U5.1 U5.2 U5.3 U6.5 U6.8 U7.A1 U7.A8 U7.F7 U7.G6 U7.G8 U7.H1 U9.1 | length 191.6
  Top Layer w0.102: 24.74,16.18 24.765,16.154
  Top Layer w0.152: C33.2@7.163,31.013 7.188,31.039 v2(7.696,31.039) ; C34.2@8.23,31.013 8.204,31.039 v2(7.696,31.039) ; C35.2@8.306,24.206 8.306,25.324 v2(8.509,25.527) 8.768,25.786 9.606,25.786 U7.A8@9.677,25.857 ; U7.G8@9.642,28.788 8.778,28.788 7.696,29.87 v2(7.696,31.039) ; v1(9.931,31.394) 10.516,31.394 C39.2@10.617,31.496 ; v2(13.15,25.786) 13.15,25.255 v2(13.564,24.841) C32.2@13.564,24.028 ; U7.H1@13.15,29.289 13.161,29.3 14.571,29.3 v2@14.582,29.289 ; v2(14.605,29.312) C31.2@15.799,29.312 ; v1(22.987,36.551) 23.817,36.551 24.845,37.579 U9.1@25.121,37.579 ; DL2.1@25.07,29.515 DL2.1@25.082,29.502 ; v1(43.088,36.217) U6.5@43.088,37.034 ; U6.8@44.871,37.404 v1(45.715,37.404) 46.663,37.404 C25.2@46.668,37.409
  Top Layer w0.254: CN7.1@2.388,43.307 2.388,44.094 2.616,44.323 7.239,44.323 8.026,43.536 9.169,43.536 9.195,43.561 9.195,41.961 9.931,41.224 v1(9.931,31.394) ; C36.2@7.239,24.206 C35.2@8.306,24.206 ; v2@14.582,29.289 v2(14.605,29.312) ; v1(15.037,31.394) 15.799,31.394 15.799,30.152 ; C31.2@15.799,29.312 15.799,30.152 ; R27.1@16.739,14.097 16.739,15.291 17.628,16.18 24.74,16.18 26.594,16.18 27.203,16.789 JP2.2@27.203,19.355 JP2.2@27.203,19.406 ; C38.2@22.987,37.338 v1(22.987,36.551) 22.987,33.724 23.476,33.235 U5.1@25.07,33.235 U5.2@25.07,32.385 U5.3@25.07,31.535 DL2.1@25.07,29.515 ; R30.1@24.765,14.326 24.765,16.154 ; DL3.1@25.069,26.238 25.082,26.251 v1(25.082,27.958) ; DL2.1@25.082,29.502 v1(25.082,27.958) ; 27.211,17.221 30.09,17.221 v1(35.608,11.703) 35.622,11.689 35.622,10.428 R5.2@35.636,10.414 ; R3.1@29.083,43.497 29.083,42.573 29.733,41.923 31.158,41.923 32.014,41.067 32.014,40.054 ; 32.002,40.014 v1(32.002,38.441) R34.1@32.824,38.441 ; R34.1@32.857,38.404 C22.2@33.881,38.404 ; C22.2@33.944,38.424 34.863,38.424 ; 34.863,38.443 34.863,38.424 ; U4.1@34.907,37.866 34.886,37.866 34.863,37.888 34.863,38.424 ; U4.10@35.197,38.412 35.185,38.424 34.863,38.424 ; U4.10@35.2,38.45 35.2,39.348 35.588,39.737 C23.2@36.142,39.737 ; C21.2@36.144,41.123 36.139,41.118 36.139,40.315 36.142,40.312 C23.2@36.142,39.737 ; C23.2@36.265,39.737 C23.2@36.142,39.737 ; U4.6@36.622,37.307 37.344,37.307 v1@37.366,37.284 ; R36.1@37.034,35.429 37.034,36.01 37.396,36.373 37.396,37.261 v1@37.358,37.3 ; v1(37.387,37.308) 37.396,37.298 C24.2@38.3,37.298 ; U6.5@43.088,37.034 U6.5@43.09,37.036 ; v1@43.106,36.212 43.106,35.317 C26.2@43.11,35.313 ; 15.799,30.152 19.301,30.152 21.496,27.958 v1(25.082,27.958)
  G2 w0.152: v2(7.696,31.039) 7.696,30.455 9.906,30.455 9.931,30.48 ; v2(8.509,25.527) 8.509,26.655 v2(10.142,28.288) v2(10.643,28.788) 10.643,29.108 9.931,29.82 9.931,30.48 ; v1@9.951,31.394 9.951,31.477 9.931,31.457 v1(9.931,31.394) 9.931,30.48 ; v2(13.564,24.841) 13.583,24.861 13.855,24.861 13.945,24.95 13.945,28.296 14.605,28.956 v2(14.605,29.312)
  G2 w0.254: v1@9.951,31.394 v1(15.037,31.394) ; v1(22.987,36.551) 29.601,36.551 31.491,38.441 v1(32.002,38.441) 35.687,38.441 36.843,37.285 36.866,37.308 v1(37.387,37.308) ; v1(25.082,27.958) 25.057,27.932 25.057,24.668 27.203,22.522 JP2.2@27.203,19.406
  Bottom Layer w0.254: v1(35.608,11.703) 35.608,8.862 39.371,5.099 51.187,5.099 JP1.1@53.137,7.048 ; v1(37.387,37.308) 39.291,35.404 42.459,35.404 42.985,35.93 42.985,35.935 43.039,35.989 43.039,36.175 v1@43.004,36.21 ; v1(43.088,36.217) 43.088,37.099 43.395,37.407 v1@45.732,37.407
VDDA: C12.2 TP4.1 U1.A6 | length 4
  Top Layer w0.152: TP4.1@59.583,28.448 60.018,28.013 C12.2@60.018,27.313 ; C12.2@60.019,27.31 60.821,27.31 61.909,26.222 62.205,26.222 U1.A6@62.22,26.223
VLDO: C19.2 JP2.3 R57.2 U3.5 | length 15.7
  Top Layer w0.152: C19.2@20.411,20.813 C19.2@20.422,20.803
  Top Layer w0.254: R57.2@10.546,22.202 11.75,22.202 12.047,21.905 17.952,21.905 18.328,21.529 18.368,21.489 18.368,20.813 C19.2@20.411,20.813 ; C19.2@20.422,20.803 21.565,20.803 22.962,19.406 JP2.3@24.663,19.406
pads on no net: CN2.5 CN2.8 CN6.4 Designator5.1 Designator6.1 U3.4 U4.7 U6.9 U6.10 U6.11 U7.A2 U7.A3 U7.B3 U7.B4 U7.B5 U7.B6 U7.B7 U7.B8 U7.C4 U7.C5 U7.C6 U7.C8 U7.D1 U7.D5 U7.D6 U7.E1 U7.E2 U7.E3 U7.E4 U7.E6 U7.E8 U7.F1 U7.F6 U7.F8 U7.G3 U7.H4 U7.H5 U7.H6

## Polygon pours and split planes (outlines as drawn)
no net on Top Overlay "-160559" (solid, pour order 0): 73.774,43.548 73.901,43.51 74.003,43.472 74.105,43.421 74.244,43.358 74.384,43.282 74.549,43.18 74.676,43.078 74.778,42.964 74.867,42.824 74.943,42.685 74.993,42.545 75.006,42.367 75.006,41.859 75.12,41.961 75.235,42.037 75.362,42.1 75.476,42.139 75.616,42.151 75.743,42.151 75.743,42.634 75.679,42.634 75.603,42.621 75.527,42.608 75.489,42.596 75.463,42.608 75.451,42.621 75.451,42.799 75.387,42.989 75.324,43.091 75.197,43.231 74.993,43.383 74.803,43.485 74.6,43.561 74.384,43.599 74.092,43.624 73.876,43.624 73.812,43.612 73.774,43.612 73.749,43.586 73.749,43.561
no net on Top Overlay "-160575" (solid, pour order 0): 72.06,43.218 72.136,43.167 72.263,43.129 72.39,43.078 72.568,43.015 72.72,42.951 72.911,42.862 73.063,42.786 73.215,42.697 73.393,42.57 73.533,42.456 73.711,42.278 73.825,42.139 73.914,41.974 74.016,41.758 74.079,41.542 74.092,41.275 74.092,40.488 74.168,40.564 74.295,40.665 74.435,40.767 74.663,40.881 74.892,40.957 75.032,40.983 75.032,41.554 74.943,41.542 74.841,41.504 74.778,41.478 74.739,41.453 74.727,41.465 74.714,41.605 74.701,41.821 74.689,41.948 74.638,42.1 74.549,42.266 74.447,42.418 74.219,42.659 74.003,42.837 73.825,42.964 73.635,43.066 73.381,43.155 73.139,43.231 72.949,43.269 72.606,43.282 72.326,43.282 72.2,43.269 72.111,43.243 72.06,43.231
no net on Top Overlay "-160574" (solid, pour order 0): 73.787,39.446 73.927,39.51 74.117,39.573 74.346,39.611 74.524,39.624 74.727,39.624 74.93,39.599 75.133,39.56 75.362,39.497 75.54,39.433 75.781,39.319 76.06,39.141 76.238,39.014 76.416,38.875 76.657,38.646 76.81,38.494 77,38.265 77.14,38.1 77.33,37.795 77.483,37.503 77.534,37.363 77.572,37.313 77.597,37.313 77.61,37.325 77.61,37.414 77.597,37.643 77.559,37.922 77.508,38.138 77.419,38.405 77.178,38.9 76.898,39.218 76.733,39.37 76.479,39.586 76.175,39.776 75.959,39.878 75.768,39.967 75.501,40.056 75.273,40.107 75.07,40.132 74.841,40.145 74.587,40.145 74.333,40.119 74.105,40.094 73.927,40.005 73.812,39.941 73.762,39.916 73.774,39.446
no net on Top Overlay "-160573" (solid, pour order 0): 70.383,42.405 70.434,42.393 70.498,42.38 70.625,42.342 70.815,42.278 71.006,42.215 71.171,42.151 71.45,42.024 71.615,41.948 71.882,41.808 72.149,41.631 72.39,41.427 72.555,41.262 72.72,41.084 72.809,40.945 72.898,40.767 73.038,40.424 73.088,40.17 73.114,39.84 73.127,39.535 73.114,39.116 73.101,38.938 73.266,39.065 73.393,39.179 73.482,39.256 73.66,39.383 73.774,39.446 73.774,39.916 73.698,39.878 73.685,39.891 73.698,40.183 73.673,40.411 73.609,40.691 73.508,40.957 73.368,41.212 73.228,41.415 73.088,41.58 72.949,41.719 72.707,41.935 72.466,42.088 72.212,42.24 71.92,42.367 71.666,42.456 71.323,42.52 71.095,42.545 70.841,42.532 70.612,42.507 70.434,42.469 70.371,42.443 70.371,42.418
no net on Top Overlay "-160571" (solid, pour order 0): 76.314,37.338 76.022,37.325 75.971,37.3 75.959,37.274 75.959,37.236 75.971,37.186 76.01,37.148 76.022,37.148 76.035,37.135 76.048,37.148 76.06,37.122 76.073,37.097 76.086,37.02 76.073,36.932 76.048,36.906 75.997,36.881 75.946,36.881 75.908,36.906 75.87,36.944 75.857,37.02 75.844,37.16 75.844,37.427 75.857,37.579 75.882,37.63 75.921,37.668 75.971,37.706 75.984,37.719 76.06,37.643 76.086,37.605 76.086,37.541 76.098,37.529 76.149,37.516 76.327,37.516 76.314,37.567 76.289,37.694 76.251,37.757 76.187,37.821 76.086,37.871 75.946,37.871 75.832,37.846 75.781,37.821 75.705,37.77 75.667,37.694 75.641,37.617 75.629,37.541 75.616,37.363 75.616,37.173 75.629,36.982 75.641,36.893 75.679,36.83 75.73,36.767 75.832,36.703 75.908,36.678 75.971,36.678 76.01,36.69 76.048,36.716 76.086,36.728 76.149,36.741 76.187,36.741 76.251,36.728 76.314,36.716
no net on Top Overlay "-160570" (solid, pour order 0): 74.765,37.452 74.765,37.846 74.879,37.846 75.146,37.833 75.311,37.821 75.374,37.795 75.425,37.744 75.451,37.681 75.463,37.617 75.476,37.516 75.476,37.452 75.235,37.452 75.248,37.503 75.248,37.541 75.235,37.592 75.184,37.643 75.12,37.668 74.993,37.668 74.993,37.452
no net on Top Overlay "-160569" (solid, pour order 0): 74.765,36.728 74.993,36.728 74.993,37.186 75.095,37.186 75.159,37.173 75.197,37.148 75.209,37.097 75.222,37.02 75.222,36.805 75.26,36.754 75.286,36.728 75.489,36.728 75.463,37.046 75.438,37.16 75.4,37.224 75.374,37.262 75.362,37.287 75.387,37.313 75.438,37.376 75.476,37.452 75.235,37.452 75.209,37.414 75.159,37.376 75.082,37.363 74.993,37.363 74.993,37.465 74.765,37.465
no net on Top Overlay "-160568" (solid, pour order 0): 74.079,36.728 73.876,36.728 73.876,37.846 74.066,37.846 74.117,37.833 74.155,37.795 74.27,37.465 74.346,37.249 74.358,37.211 74.397,37.211 74.409,37.236 74.409,37.846 74.612,37.846 74.612,36.728 74.346,36.728 74.143,37.338 74.117,37.363 74.092,37.363 74.079,37.351
no net on Top Overlay "-160567" (solid, pour order 0): 73.469,37.135 73.711,37.148 73.736,37.148 73.736,37.224 73.724,37.363 73.698,37.452 73.647,37.541 73.596,37.579 73.52,37.592 73.482,37.592 73.482,37.49 73.52,37.478 73.558,37.427 73.584,37.338 73.571,37.262 73.52,37.236 73.469,37.236
no net on Top Overlay "-160566" (solid, pour order 0): 73.571,36.893 73.596,36.932 73.609,36.97 73.635,36.995 73.685,37.008 73.711,36.995 73.724,36.982 73.724,36.957
no net on Top Overlay "-160565" (solid, pour order 0): 73.711,36.995 73.482,36.805 73.393,36.817 73.368,36.855 73.33,36.957 73.317,37.059 73.304,37.135 73.495,37.135 73.495,37.236 73.533,37.249 73.406,37.236 73.343,37.249 73.317,37.274 73.317,37.313 73.343,37.376 73.368,37.427 73.406,37.465 73.444,37.49 73.495,37.49 73.495,37.592 73.406,37.592 73.317,37.554 73.241,37.49 73.215,37.427 73.177,37.313 73.165,37.211 73.165,37.033 73.19,36.906 73.228,36.817 73.292,36.754 73.368,36.703 73.431,36.678 73.469,36.678 73.533,36.69 73.609,36.741 73.698,36.83 73.724,36.893 73.724,36.957 73.711,36.957
no net on Top Overlay "-160564" (solid, pour order 0): 72.479,37.567 72.606,37.567 72.606,37.071 72.619,36.944 72.619,36.868 72.657,36.83 72.707,36.817 72.758,36.817 72.796,36.843 72.847,36.893 72.86,36.982 72.86,37.148 72.873,37.554 73.012,37.567 73.012,36.716 72.974,36.728 72.911,36.741 72.873,36.728 72.822,36.716 72.784,36.703 72.746,36.69 72.695,36.678 72.619,36.69 72.555,36.728 72.504,36.792 72.492,36.83 72.479,36.919
no net on Top Overlay "-160563" (solid, pour order 0): 71.336,37.363 71.336,37.782 71.349,37.821 71.387,37.833 71.425,37.846 71.488,37.846 71.73,37.833 71.819,37.821 71.882,37.782 71.945,37.719 71.971,37.655 71.984,37.579 71.971,37.478 71.806,37.478 71.819,37.554 71.819,37.617 71.806,37.668 71.78,37.694 71.691,37.719 71.59,37.732 71.526,37.732 71.501,37.706 71.488,37.592 71.488,37.363
no net on Top Overlay "-160562" (solid, pour order 0): 71.349,36.741 71.603,36.728 71.704,36.728 71.819,36.741 71.895,36.779 71.971,36.855 72.009,36.932 72.022,37.033 72.022,37.071 71.996,37.16 71.958,37.224 71.907,37.274 71.857,37.313 71.92,37.376 71.958,37.44 71.971,37.478 71.806,37.478 71.78,37.414 71.73,37.376 71.666,37.363 71.336,37.363 71.336,37.211 71.488,37.211 71.488,37.236 71.666,37.236 71.73,37.224 71.78,37.198 71.831,37.135 71.857,37.084 71.869,37.02 71.844,36.944 71.806,36.893 71.768,36.855 71.717,36.83 71.488,36.83 71.488,37.211 71.336,37.211
no net on Top Overlay "-160561" (solid, pour order 0): 72.174,36.728 72.314,36.741 72.314,37.833 72.174,37.846
no net on Top Overlay "-160560" (solid, pour order 0): 75.73,42.151 75.882,42.139 76.048,42.1 76.213,42.024 76.391,41.91 76.53,41.796 76.632,41.694 76.759,41.554 76.873,41.402 76.975,41.237 77.064,41.059 77.102,40.996 77.114,40.996 77.14,41.021 77.127,41.224 77.102,41.402 77.064,41.554 77.025,41.656 76.886,41.897 76.746,42.075 76.67,42.164 76.543,42.278 76.403,42.393 76.289,42.469 76.213,42.52 76.022,42.583 75.895,42.621 75.794,42.634 75.73,42.634
no net on Top Overlay "-160558" (solid, pour order 0): 75.032,40.983 75.133,40.996 75.248,40.996 75.4,40.983 75.59,40.945 75.755,40.894 75.933,40.818 76.098,40.742 76.238,40.665 76.429,40.526 76.606,40.373 76.695,40.284 76.835,40.157 76.975,39.992 77.076,39.865 77.203,39.675 77.343,39.446 77.406,39.268 77.457,39.154 77.47,39.129 77.47,39.116 77.495,39.129 77.508,39.167 77.521,39.268 77.534,39.522 77.483,39.776 77.432,39.954 77.305,40.234 77.178,40.437 77.013,40.64 76.772,40.881 76.505,41.097 76.276,41.262 76.022,41.377 75.73,41.504 75.489,41.554 75.26,41.567 75.082,41.567 75.032,41.554
GND on Top Layer "Mid-Layer 1-GND" (solid, pour order 54): 0.128,53.896 80.169,53.896 80.169,36.573 55.982,36.573 47.194,36.573 47.194,15.059 80.159,15.059 80.169,0.124 0.128,0.124
GND_RF on Top Layer "Mid-Layer 1-GND_RF" (solid, pour order 48): 80.147,15.508 47.642,15.508 47.642,36.064 56.554,36.064 80.184,36.064
no net on Top Layer "NONET_TOP_LAYER_P040" (solid, pour order 40): 78.906,25.73 78.906,25.279 83.223,25.279 84.543,26.189 85.045,26.189 85.045,27.189 86.845,27.189 86.845,12.789 88.055,12.789 88.055,36.369 81.885,36.369 81.885,35.389 80.159,35.389 80.159,34.389 81.885,34.389 81.885,30.189 80.159,30.189 80.159,29.189 83.175,29.189 83.175,34.189 85.845,34.189 85.845,28.389 85.045,28.389 85.045,29.389 83.835,29.389 83.835,26.26 83.067,25.73
no net on Top Layer "Top Layer-No Net" (solid, pour order 44): 80.38,29.057
GND on Top Layer "Top Layer-GND 1" (solid, pour order 12): -5.448,53.457
GND_RF on G1 "Mid-Layer 1-GND_RF" (solid, pour order 4): 80.148,15.53 47.638,15.53 47.638,36.086 56.335,36.086 56.335,36.18 56.429,36.086 80.186,36.086
GND on G1 "Mid-Layer 1-GND" (solid, pour order 34): 0.127,54.153 80.169,54.153 80.169,36.579 56.007,36.579 47.193,36.579 47.193,15.049 80.158,15.049 80.169,0.127 0.127,0.127
GND_RF on Bottom Layer "Mid-Layer 1-GND_RF" (solid, pour order 52): 80.148,15.505 47.637,15.505 47.637,36.061 56.334,36.061 56.334,36.155 56.428,36.061 80.185,36.061
GND on Bottom Layer "Bottom Layer-GND" (solid, pour order 20): 0.001,54.026 80.168,54.026 80.168,36.656 55.989,36.656 47.175,36.656 47.175,15.047 79.935,15.047 79.946,0 0.001,0
GND_RF on G2 "Mid-Layer 1-GND_RF" (solid, pour order 50): 80.147,15.516 47.637,15.516 47.637,36.073 56.334,36.073 56.334,36.167 56.428,36.073 80.184,36.073
GND on G2 "Mid-Layer 1-GND" (solid, pour order 36): 0.127,53.899 80.169,53.899 80.169,36.576 55.982,36.576 47.193,36.576 47.193,15.062 80.158,15.062 80.169,0.127 0.127,0.127

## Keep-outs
Keep-Out Layer:
  lines w0.026: 0,0 0,54.026 80.169,54.026 90.813,43.381 90.813,10.645 80.169,0 0,0

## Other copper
Top Layer:
  rectangle net NetC43_2: 79.013,25.357 79.016,25.685
  pour cut-out: 65.425,22.274 65.436,22.285 68.34,22.285 68.34,18.673 65.419,18.673
  pour cut-out: 60.454,24.229 60.74,24.229 60.74,24.94 60.731,24.95 60.457,24.95
  pour cut-out: 64.176,25.529 64.87,25.529 64.885,25.545 64.885,26.132 64.176,26.132
  region net GND_RF: 64.868,24.737 64.678,24.963 64.578,24.963 64.578,25.027 64.674,25.123 64.732,25.065 65.688,25.065 65.851,25.065 65.695,25.038 65.695,24.85 65.379,24.262
  pour cut-out: 55.425,23.776 59.689,23.776 59.689,24.944 55.43,24.944
  pour cut-out: 75.133,27.138 75.845,27.138 75.845,27.421 75.134,27.421
  pour cut-out: 72.681,25.151 72.967,25.151 72.967,25.862 72.958,25.872 72.684,25.872
  pour cut-out: 69.457,24.586 69.748,24.586 69.748,26.219 69.727,26.239 69.465,26.239
  pour cut-out: 65.784,20.214 65.784,16.736 68.486,16.736 70.747,16.736 70.747,20.214
  pour cut-out: 55.426,24.192 55.426,18.672 66.454,18.672 66.454,24.192
  region net NetC30_2: 64.759,25.502 65.006,25.577 65.471,25.676 65.471,25.17 65.276,25.208 64.759,25.35
  pour cut-out: 77.097,25.148 77.383,25.148 77.383,25.834 77.364,25.853 77.1,25.853
  pour cut-out: 66.121,25.069 66.407,25.069 66.407,25.78 66.398,25.789 66.124,25.789
  region: 87.304,35.939
  region: 87.303,35.94
  pour cut-out: 56.967,23.681
  pour cut-out: 95.039,39.675
  region: 80.912,35.621
G1:
  pour cut-out: 62.455,24.93 62.446,24.367 64.399,24.367 64.397,24.951 62.467,24.951
  pour cut-out: 64.171,25.504 64.181,25.494 64.831,25.494 64.831,26.046 64.824,26.053 64.819,26.048 64.176,26.048
  pour cut-out: 64.188,25.693 64.188,25.068 63.941,25.068 63.939,25.69
Bottom Layer:
  pour cut-out: 63.922,25.356 63.908,25.045 64.151,25.045 64.159,25.356
  pour cut-out: 61.067,24.821
  pour cut-out: 62.902,24.92 64.415,24.926 64.415,24.376 62.902,24.376

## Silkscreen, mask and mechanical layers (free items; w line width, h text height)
Top Overlay:
  circle w0.127: c73.952,39.802 r4.751
  lines w0.152: 11.148,25.076 11.148,25.301
  lines w0.254: 41.467,20.016 41.467,31.993 44.972,31.993 44.972,20.016 42.711,20.016 41.467,20.016 ; 53.965,16.405 57.3,16.405 57.322,16.426 74.897,16.426 74.897,28.452 66.726,28.452 66.726,30.066 56.363,30.066 56.363,30.061 53.965,30.061 53.965,16.405
  text "PA1" at 56.515,46.99 h0.95 r90
  text "PA7" at 54.229,46.863 h0.95 r90
  text "GND" at 32.131,46.736 h0.95 r90
  text "PB9" at 42.291,46.736 h0.95 r90
  text "PB8" at 44.958,46.736 h0.95 r90
  text "PA5" at 47.371,46.736 h0.95 r90
  text "PA4" at 51.435,46.736 h0.95 r90
  text "PA6" at 58.928,46.736 h0.95 r90
  text "PB0" at 64.008,46.736 h0.95 r90
  text "PA9" at 66.675,46.736 h0.95 r90
  text "PA8" at 69.215,46.736 h0.95 r90
  text "PA11" at 24.511,46.101 h0.95 r90
  text "PB14" at 27.178,46.101 h0.95 r90
  text "VBAT" at 29.591,45.974 h0.95 r90
  text "PA13" at 34.671,45.974 h0.95 r90
  text "PA14" at 37.211,45.974 h0.95 r90
  text "PA15" at 39.751,45.974 h0.95 r90
  text "PA13" at 61.468,45.974 h0.95 r90
  text "0" at 28.169,38.075 h0.23
  text "O" at 15.951,37.579 h0.19
  text "BLUENRG-LP CSP49" at 48.677,34.05 h1.14
  text "O" at 24.765,33.782 h0.18
  text "vers 3" at 48.708,32.873 h0.76
  text "O" at 13.462,25.578 h0.18
  text "o" at 61.806,23.502 h0.25
  text "USB" at 25.019,21.031 h0.95 r90
  text "BAT" at 30.226,21.031 h0.95 r90
  text "FOR EVALUATION ONLY" at 42.571,20.448 h0.6 r90
  text "NOT FCC APPROVED" at 43.587,20.448 h0.6 r90
  text "FOR RESALE" at 44.603,20.448 h0.6 r90
  text "1" at 54.635,6.502 h0.57
  text "1" at 41.961,6.185 h0.57
  text "1" at 51.054,4.953 h0.57
  text "1" at 46.939,4.902 h0.57
  text "PB5" at 56.642,4.699 h0.95 r90
  text "VBAT" at 41.427,4.651 h0.95 r90
  text "PA10" at 33.608,4.595 h0.95 r90
  text "VBAT" at 36.195,4.572 h0.95 r90
  text "RSTN" at 38.735,4.572 h0.95 r90
  text "PB2" at 59.055,4.572 h0.95 r90
  text "PB3" at 61.595,4.572 h0.95 r90
  text "PA12" at 64.135,4.572 h0.95 r90
  text "PB7" at 66.675,4.572 h0.95 r90
  text "PB4" at 69.215,4.572 h0.95 r90
  text "GND" at 43.942,4.343 h0.95
  text "GND" at 47.625,4.318 h0.95
Mechanical 1:
  lines w0.025: -0.013,0 ccw(c0,0) 0,-0.013 ; -0.013,0 ccw(c0,0) 0,-0.013 ; -0.013,0 -0.013,54.026 ; -0.013,54.026 cw(c0,54.026) 0,54.039 ; -0.013,54.026 cw(c0,54.026) 0,54.039 ; 0,-0.013 80.169,-0.013 ; 0,54.039 80.169,54.039 ; 80.169,-0.013 ccw(c80.169,0) 80.178,-0.009 ; 80.169,-0.013 ccw(c80.169,0) 80.178,-0.009 ; 80.169,54.039 cw(c80.169,54.026) 80.178,54.035 ; 80.169,54.039 cw(c80.169,54.026) 80.178,54.035 ; 80.178,-0.009 90.783,10.596 90.842,10.866 90.842,43.371 80.178,54.035 ; 0.013,0.013 80.163,0.013 90.822,10.671 90.822,43.355 80.163,54.013 0.013,54.013 0.013,0.013 ; 88.875,8.688 ccw(c88.866,8.697) 88.879,8.697 cw(c88.866,8.697) 88.875,8.688 ; 88.875,45.338 cw(c88.866,45.329) 88.879,45.329 ccw(c88.866,45.329) 88.875,45.338
Mechanical 13:
  lines w0.025: 13.391,25.33 13.641,25.58
Drill Drawing:
  lines w0.254: 7.023,-82.194 101.892,-82.194 ; 7.023,-82.067 7.023,-36.347 ; 7.023,-36.22 101.892,-36.22 ; 7.15,-76.987 101.765,-76.987 ; 7.15,-73.177 101.765,-73.177 ; 7.15,-69.367 101.765,-69.367 ; 7.15,-65.557 101.765,-65.557 ; 7.15,-61.747 101.765,-61.747 ; 7.15,-57.937 101.765,-57.937 ; 7.15,-54.127 101.765,-54.127 ; 7.15,-50.317 101.765,-50.317 ; 7.15,-46.507 101.765,-46.507 ; 7.15,-46.38 101.765,-46.38 ; 7.15,-41.427 101.765,-41.427 ; 7.15,-41.3 101.765,-41.3 ; 11.151,-63.652 12.421,-63.652 ; 11.151,-56.667 12.421,-55.397 ; 11.151,-55.397 12.421,-56.667 ; 11.151,-52.222 12.421,-52.222 ; 11.786,-64.287 11.786,-63.017 ; 11.786,-52.857 11.786,-51.587 ; 16.421,-76.987 16.421,-41.427 ; 16.548,-76.987 16.548,-41.427 ; 37.863,-76.987 37.863,-41.427 ; 58.352,-82.067 58.352,-41.427 ; 72.449,-82.067 72.449,-41.427 ; 101.892,-82.067 101.892,-36.347 ; 11.151,-68.097 11.151,-66.827 ; 11.151,-68.097 12.421,-68.097 ; 11.151,-68.097 12.421,-66.827 ; 11.151,-66.827 12.421,-66.827 ; 11.151,-66.827 12.421,-68.097 ; 12.421,-68.097 12.421,-66.827 ; 7.15,-82.067 101.765,-82.067 101.765,-36.347 7.15,-36.347 7.15,-82.067 ; 11.151,-75.336 11.151,-74.828 11.786,-75.463 12.421,-74.828 12.421,-75.336 11.786,-74.701 11.151,-75.336 ; 11.151,-71.272 11.786,-70.637 12.421,-71.272 11.786,-71.907 11.151,-71.272 ; 11.151,-59.842 11.151,-59.207 11.786,-59.207 11.786,-60.477 12.421,-60.477 12.421,-59.842 11.151,-59.842 ; 11.151,-52.857 11.151,-51.587 12.421,-51.587 12.421,-52.857 11.151,-52.857 ; 11.151,-48.666 11.151,-48.158 11.532,-47.777 12.04,-47.777 12.421,-48.158 12.421,-48.666 12.04,-49.047 11.532,-49.047 11.151,-48.666
  text ".Legend" at 7.15,-36.347 h0.64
